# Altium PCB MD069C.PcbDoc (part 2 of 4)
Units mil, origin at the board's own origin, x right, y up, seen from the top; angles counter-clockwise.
Board outline 4569 x 3239 mil, 4 copper layers (Top Layer, Signal Layer 1, Signal Layer 2, Bottom Layer), stack 61.2 mil thick; 192 components, 101 nets, 567 pads, 224 vias.
Unrouted connection lines stored in the file: 7.

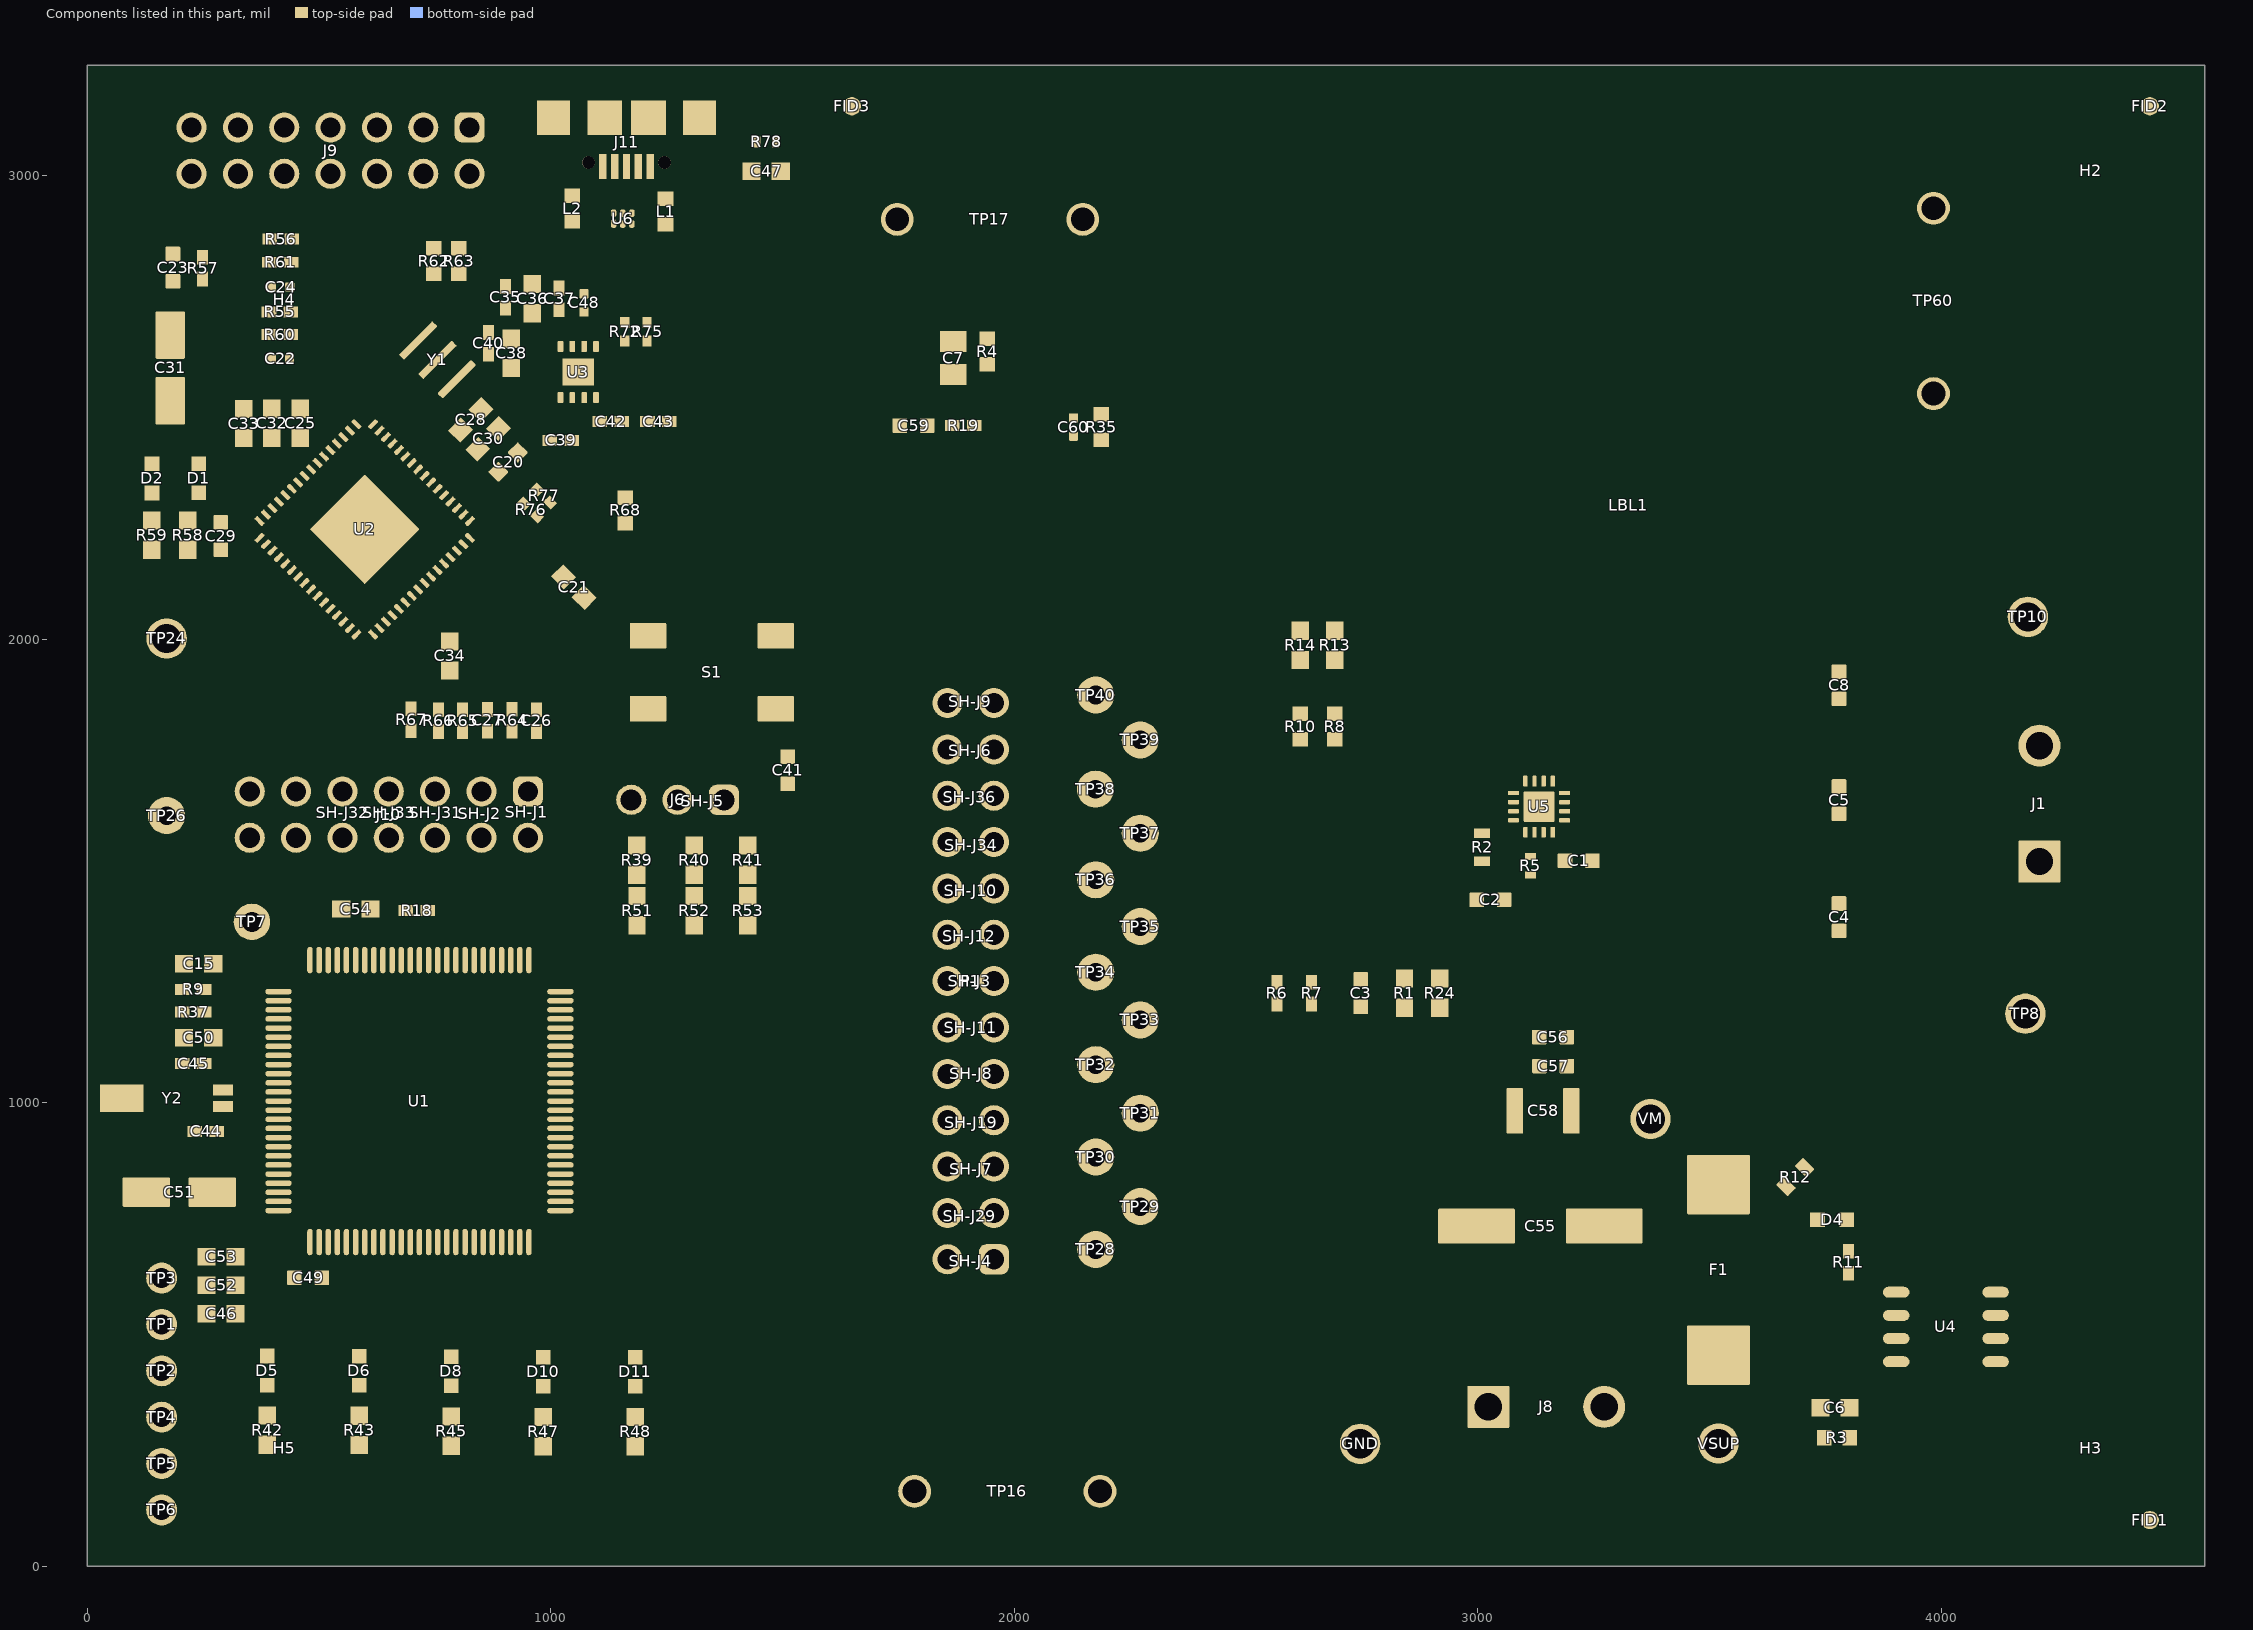
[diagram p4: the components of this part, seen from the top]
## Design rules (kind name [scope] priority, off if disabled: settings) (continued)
PolygonConnect PolygonConnect_5 [All vs IsNamedPolygon('TOP_LAYER_VM_P044')] p90: connectstyle=Direct reliefconductorwidth=10 reliefentries=4 polygonreliefangle="90 Angle" airgapwidth=10
PolygonConnect PolygonConnect_4 [All vs IsNamedPolygon('TOP_LAYER_VM_P046')] p91: connectstyle=Direct reliefconductorwidth=10 reliefentries=4 polygonreliefangle="90 Angle" airgapwidth=10
PolygonConnect PolygonConnect_3 [All vs IsNamedPolygon('TOP_LAYER_GND_P036') Or  IsNamedPolygon('TOP_LAYER_OUT2_P040') Or  IsNamedPolygon('TOP_LAYER_OUT1_P038')] p92: connectstyle=Direct reliefconductorwidth=10 reliefentries=4 polygonreliefangle="90 Angle" airgapwidth=10
PolygonConnect PolygonConnect_2 [InNet('EZFET_VBUS') vs IsNamedPolygon('TOP_LAYER_EZFET_VBUS_P008')] p93: connectstyle=Direct reliefconductorwidth=10 reliefentries=4 polygonreliefangle="90 Angle" airgapwidth=10
PolygonConnect PolygonConnect_1 [InNetClass('Power-Net') vs IsNamedPolygon('TOP_LAYER_EZFET_USB_SHIELD_P201')] p94: connectstyle=Direct reliefconductorwidth=10 reliefentries=4 polygonreliefangle="90 Angle" airgapwidth=10
PolygonConnect [All] p95: connectstyle=Direct reliefconductorwidth=10 reliefentries=4 polygonreliefangle="90 Angle" airgapwidth=10
RoutingVias ThermalPadVias [IsVia and InAnyComponent] p1: holewidth=7.87 width=19.68 viastyle="Through Hole" minholewidth=7.87 minwidth=19.68 maxholewidth=12.99 maxwidth=23.62
RoutingVias [All] p2: holewidth=16 width=34 viastyle="Through Hole" minholewidth=7.87 minwidth=26 maxholewidth=40 maxwidth=65
SilkToBoardRegionClearance [Not ((IsComment or IsDesignator) And (Hide <> 'False')) and not InRegion(1000,500,4000,800)] p1:
SilkToSilkClearance SilkToSilkClearance_Pb-FreeLogo [(HasFootprint('Pb-Free_Overlay_Medium') OR HasFootprint('Pb-Free_Overlay_Small')) vs (HasFootprint('Pb-Free_Overlay_Medium') OR HasFootprint('Pb-Free_Overlay_Small'))] p1: silktosilkclearance=0
SilkToSilkClearance [All] p2: silktosilkclearance=3.94
SilkToSolderMaskClearance SilkToComponentPadClearance [(IsPad or IsFill or IsRegion) and InAnycomponent] p1: minsilkscreentomaskgap=5 clearancetoexposedcopper=TRUE
SilkToSolderMaskClearance "Silk to Solder Mask Opening" [All] p2: minsilkscreentomaskgap=3.94 clearancetoexposedcopper=FALSE
SolderMaskExpansion [All] p1: expansion=1.97 istentingtop=FALSE
UnRoutedNet [All] p1: checkbadconnections=TRUE
Width [All] p1: maxlimit=65 minlimit=4 preferedwidth=15 minimp=50.000000 maximp=50.000000 favimp=50.000000 checkconnectedcopper=TRUE
14 further rules are at their usual default settings.

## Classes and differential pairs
component class FiducialMark: FID1 FID2 FID3
component class MD069C_Hardware: !PCB1 FID1 FID2 FID3 H2 H3 H4 H5 LBL1 Logo1 Logo2 Logo3 Logo4 LOGO5 ZZ1 ZZ2 ZZ3 ZZ4
component class MD069C: C1 C2 C3 C4 C5 C6 C7 C8 C15 C41 C44 C45 C46 C49 C50 C51 C52 C53 C54 C55 C56 C57 C58 C59 C60 D4 D5 D6 D8 D10 D11 F1 GND J1 J6 J8 P1 R1 R2 R3 R4 R5 R6 R7 R8 R9 R10 R11 R12 R13 R14 R18 R19 R24 R35 R37 R39 R40 R41 R42 R43 R45 R47 R48 R51 R52 R53 S1 SH-J1 SH-J2 SH-J3 SH-J4 SH-J5 SH-J6 SH-J7 SH-J8 SH-J9 SH-J10 SH-J11 SH-J12 SH-J19 SH-J36 TP1 TP2 TP3 TP4 TP5 TP6 TP7 TP8 TP10 TP16 TP17 TP24 TP26 TP28 TP29 TP30 TP31 TP32 TP33 TP34 TP35 TP36 TP37 TP38 TP39 TP40 TP60 U1 U4 U5 VM VSUP Y2
component class Shunt: SH-J1 SH-J2 SH-J3 SH-J4 SH-J5 SH-J6 SH-J7 SH-J8 SH-J9 SH-J10 SH-J11 SH-J12 SH-J19 SH-J29 SH-J31 SH-J32 SH-J33 SH-J34 SH-J36
net class Power-Net: EZFET_VBUS EZFET_VCC GND MCU_3V3
component class Header: J6 J9 J10
component class MD069C_ezFET: C20 C21 C22 C23 C24 C25 C26 C27 C28 C29 C30 C31 C32 C33 C34 C35 C36 C37 C38 C39 C40 C42 C43 C47 C48 D1 D2 J9 J10 J11 L1 L2 R55 R56 R57 R58 R59 R60 R61 R62 R63 R64 R65 R66 R67 R68 R72 R75 R76 R77 R78 SH-J29 SH-J31 SH-J32 SH-J33 SH-J34 U2 U3 U6 Y1
component class Logo: Logo2
component class AssemblyNote: ZZ1 ZZ2 ZZ3 ZZ4
component class Label: LBL1
differential pair USB_D: +USB_D_P -USB_D_N
differential pair EZFET_D: +EZFET_D_P -EZFET_D_N

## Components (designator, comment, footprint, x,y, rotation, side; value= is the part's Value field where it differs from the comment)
C1 "885012206120" FP-885012206120_0603-MFG 3217.89,1522.41 r180 top value=100nF
C2 "885012206120" FP-885012206120_0603-MFG 3027.54,1437.94 r0 top value=100nF
C3 "885012006085" FP-885012006085_0603-MFG 2747.83,1237 r90 top value=1nF
C4 "885012006085" FP-885012006085_0603-MFG 3779.61,1400.57 r90 top value=1nF
C5 "885012006085" FP-885012006085_0603-MFG 3779.61,1653.04 r270 top value=1nF
C6 "885012206095" 0603 3770.83,342.3 r0 top value=0.1uF
C7 "885012107011" 0805_150 1868.75,2606.85 r270 top value=22uF
C8 "885012006085" FP-885012006085_0603-MFG 3779.61,1901.04 r270 top value=1nF
C15 "885012206095" 0603 240.63,1300.54 r180 top value=0.1uF
C20 "885012106012" FP-885012106012_0603-MFG 908.28,2382.21 r225 top value=4.7µF
C21 "885012206095" 0603 1050.3,2112.7 r315 top value=0.1uF
C22 "885012005058" FP-885012005058_0402-MFG 417.27,2605.12 r0 top value=33pF
C23 "885012006085" FP-885012006085_0603-MFG 185.39,2801.89 r90 top value=1nF
C24 "885012005058" FP-885012005058_0402-MFG 417.71,2759.93 r0 top value=33pF
C25 "885012206095" 0603 459.95,2466.1 r90 top value=0.1uF
C26 "885012005055" 0402 969.55,1824.77 r270 top value=10pF
C27 "885012005055" 0402 863.56,1825 r270 top value=10pF
C28 "885012206048" 0603 827.93,2473.48 r45 top value=0.22uF
C29 "885012106008" FP-885012106008_0603-MFG 288.85,2222.71 r270 top value=470nF
C30 "885012206048" 0603 865.13,2432.41 r45 top value=0.22uF
C31 "875105240001" FP-875105240001_SMT_CAP_4MM3_4MM3-MFG 179.54,2585.63 r270 top value=10µF
C32 "885012206095" 0603 398.51,2466.1 r90 top value=0.1uF
C33 "885012206095" 0603 338.36,2465.67 r90 top value=0.1uF
C34 "885012206095" 0603 782.72,1964.12 r90 top value=0.1uF
C35 "885012105012" 0402 902.39,2737.6 r90 top value=1uF
C36 "885012206095" 0603 960.11,2735.17 r90 top value=0.1uF
C37 "885012205031" 0402 1018.24,2734.43 r90 top value=0.01uF
C38 "885012106018" 0603 914.83,2617.06 r90 top value=2.2uF
C39 "885012205031" 0402 1021.71,2429.23 r0 top value=0.01uF
C40 "885012105012" 0402 865.88,2638.47 r90 top value=1uF
C41 "885012006085" FP-885012006085_0603-MFG 1511.79,1717.67 r270 top value=1nF
C42 "885012005055" 0402 1129.9,2469.66 r180 top value=10pF
C43 "885012005055" 0402 1232.69,2469.66 r0 top value=10pF
C44 "885012005055" 0402 255.9,938.79 r0 top value=10pF
C45 "885012005055" 0402 228.65,1084.82 r180 top value=10pF
C46 "885012206095" 0603 289.02,545.23 r0 top value=0.1uF
C47 "885012206048" 0603 1465,3010.03 r0 top value=0.22uF
C48 "885012205018" FP-885012205018_0402-MFG 1072,2726 r90 top value=100nF
C49 "885012106008" FP-885012106008_0603-MFG 476.94,622.9 r0 top value=470nF
C50 "885012206095" 0603 240.63,1140.4 r180 top value=0.1uF
C51 "875105240001" FP-875105240001_SMT_CAP_4MM3_4MM3-MFG 198.98,807.41 r0 top value=10µF
C52 "885012206095" 0603 289.02,606.31 r180 top value=0.1uF
C53 "885012206095" 0603 289.02,667.92 r180 top value=0.1uF
C54 "885012206095" 0603 580.07,1418.17 r180 top value=0.1uF
C55 "865060653010" WCAP-ASLL_800x1050 3135.27,734.32 r180 top value=100uF
C56 "885012206120" FP-885012206120_0603-MFG 3162.41,1142.05 r0 top value=100nF
C57 "885012006085" FP-885012006085_0603-MFG 3162.93,1079.49 r0 top value=1nF
C58 "885012209069" FP-885012209069_1210-MFG 3141.12,982.93 r0 top value=1µF
C59 "885012006085" FP-885012006085_0603-MFG 1783,2461 r0 top value=1nF
C60 "885012005080" FP-885012005080_0402-MFG 2128,2458 r270 top value=100pF
D1 "150060RS75000" WL-SMCW_RED 241.42,2347.56 r270 top value=Red
D2 "150060VS75000" WL-SMCW_GREEN 140.2,2347.34 r270 top value=Green
D4 "150060VS75000" WL-SMCW_GREEN 3764.65,748.22 r180 top value=Green
D5 "150060VS75000" WL-SMCW_GREEN 388.79,422.48 r90 top value=Green
D6 "150060VS75000" WL-SMCW_GREEN 587.33,422 r90 top value=Green
D8 "150060VS75000" WL-SMCW_GREEN 785.86,421 r90 top value=Green
D10 "150060YS75000" WL-SMCW_YELLOW 984.4,420 r90 top value=Yellow
D11 "150060SS75000" WL-SMCW_RED 1182.94,420 r90 top value="Super Red"
F1 "0463030.ER" Fuse_0463 3519.57,639.72 r90 top
FID1 "Fiducial" Fiducial10-20 4450,100 r0 top
FID2 "Fiducial" Fiducial10-20 4450,3150 r0 top
FID3 "Fiducial" Fiducial10-20 1650,3150 r0 top
GND "5011" Keystone5011 2746.6,264.49 r270 top
H2 "SJ61A1" Bumpon_SJ61A1 4322.71,3010.82 r180 bottom
H3 "SJ61A1" Bumpon_SJ61A1 4322.71,254.91 r180 bottom
H4 "SJ61A1" Bumpon_SJ61A1 425.07,2733 r180 bottom
H5 "SJ61A1" Bumpon_SJ61A1 425.07,254.91 r180 bottom
J1 "691250610002" FP-691250610002_CONN_TERM_BLOCK2-MFG 4276.9,1633.9 r90 top
J6 "61300311121" WURTH_61300311121 1274,1653.91 r180 top
J8 "691250610002" FP-691250610002_CONN_TERM_BLOCK2-MFG 3136.18,279.35 r0 top
J9 "61301421121" Wurth_61301421121 525.43,3054.4 r270 top
J10 "61301421121" Wurth_61301421121 651,1622.02 r270 top
J11 "629105136821" 629105136821 1163.82,3125.32 r180 top
L1 "742792621" 0603L 1247.92,2922.74 r270 top value="140 ohm"
L2 "742792621" 0603L 1046.9,2929.31 r270 top value="140 ohm"
LBL1 "THT-14-423-10" Label_650x200 3324.42,2289.31 r0 top
Logo1 "CE Mark" CE_Mark_5mm 2152,2646 r0 top
Logo2 "Texas Instruments" TI_Stacked_Overlay_Medium 3108.15,2928.68 r0 top
Logo3 "FCC disclaimer" FCC_disclaimer 1552.47,194 r0 top
Logo4 "WEEE logo" WEEE_Minimum 2438,2655 r0 top
LOGO5 "CAUTION HOT SURFACE" IEC_HotSurface_Small 3513.09,1628.59 r0 top
P1 "61302621121" 61302621121 1906.3,1262.7 r90 top
R1 "RC0603JR-0710KL" 0603 2842,1237 r270 top value=10k
R2 "ERJ-3EKF1501V" 0603S 3009.48,1551.55 r270 top value=1.50k
R3 "Resistor" 0603L 3775.18,277.13 r180 top value=0
R4 "Resistor" 0603L 1942,2621 r90 top value=0
R5 "RC0402JR-070RL" 0402S 3113.71,1512 r90 top value=0
R6 "CRCW04022K21FKED" 0402 2567,1237 r270 top value=2.21k
R7 "CRCW04022K21FKED" 0402 2642,1237 r270 top value=2.21k
R8 "Resistor" 0603L 2692,1812 r90 top value=0
R9 "CRCW040210R0FKED" 0402 228.65,1245.03 r180 top value=10.0
R10 "Resistor" 0603L 2617,1812 r90 top value=0
R11 "CRCW0402680RJNED" 0402 3799.56,656.38 r90 top value=680
R12 "ERJ-3EKF5602V" FP-ERJ-3EKF5602V_0603-MFG 3685.21,840.11 r225 top value=56k
R13 "RC0603JR-0710KL" 0603 2692,1987 r90 top value=10k
R14 "RC0603JR-0710KL" 0603 2617,1987 r90 top value=10k
R18 "CRCW040247K0JNED" 0402 710.98,1414.72 r0 top value=47k
R19 "CRCW040247K0JNED" 0402 1890.54,2461.14 r0 top value=47k
R24 "RC0603JR-0710KL" 0603 2918.44,1237 r270 top value=10k
R35 "CRCW06034K99FKEA" 0603L 2188,2458 r270 top value=4.99k
R37 "CRCW040210R0FKED" 0402 228.65,1195.71 r0 top value=10.0
R39 "RC0603JR-0710KL" 0603 1186.18,1523.73 r270 top value=10k
R40 "RC0603JR-0710KL" 0603 1310,1523.73 r270 top value=10k
R41 "RC0603JR-0710KL" 0603 1425,1523.73 r270 top value=10k
R42 "RC0603JR-07560RL" 0603 388.5,294.21 r90 top value=560
R43 "CRCW0603330RJNEA" 0603 587.12,293.74 r90 top value=330
R45 "CRCW0603330RJNEA" 0603 785.74,291.74 r90 top value=330
R47 "CRCW0603330RJNEA" 0603 984.35,290.74 r90 top value=330
R48 "CRCW0603330RJNEA" 0603 1182.97,290.74 r90 top value=330
R51 "RC0603JR-0710KL" 0603 1186.54,1414.73 r270 top value=10k
R52 "RC0603JR-0710KL" 0603 1310,1414.73 r270 top value=10k
R53 "RC0603JR-0710KL" 0603 1425,1414.73 r270 top value=10k
R55 "RC0402FR-07220KL" 0402 416.06,2706.57 r180 top value=220k
R56 "CRCW0402240KFKED" 0402 417.71,2863.28 r180 top value=240k
R57 "CRCW040247K0JNED" 0402 249.39,2801.11 r270 top value=47k
R58 "RC0603JR-07470RL" 0603 217.05,2224.98 r90 top value=470
R59 "RC0603JR-07560RL" 0603 139.47,2224.94 r90 top value=560
R60 "RC0402FR-07220KL" 0402 415.82,2657.42 r0 top value=220k
R61 "CRCW0402150KFKED" 0402 417.32,2813.56 r0 top value=150k
R62 "Resistor" 0603L 748.08,2816.24 r270 top value=0
R63 "Resistor" 0603L 801.84,2815.99 r270 top value=0
R64 "CRCW040210R0FKED" 0402 916.87,1825.29 r270 top value=10.0
R65 "CRCW040210R0FKED" 0402 810.39,1824.44 r270 top value=10.0
R66 "CRCW040210R0FKED" 0402 757.89,1824.8 r270 top value=10.0
R67 "CRCW040210R0FKED" 0402 698.9,1826.38 r270 top value=10.0
R68 "Resistor" 0603L 1161.5,2278.36 r90 top value=0
R72 "CRCW040227R0JNED" 0402L 1159.94,2663.57 r270 top value=27
R75 "CRCW040227R0JNED" 0402L 1208.37,2663.57 r270 top value=27
R76 "CRCW04021K40FKED" 0402L 956.89,2279.33 r315 top value=1.40k
R77 "CRCW04021M00JNED" 0402L 985.35,2309.35 r135 top value=1.0Meg
R78 "CRCW040233K0JNED" 0402S 1465,3073 r180 top value=33k
S1 "430481025816" FP-430481025816_SMT_SW_6MM2_6MM2-MFG 1348,1929 r180 top
SH-J1 "60900213421" Wurth_60900213421 948.09,1626.66 r90 top
SH-J2 "60900213421" Wurth_60900213421 847.52,1624.26 r90 top
SH-J3 "60900213421" Wurth_60900213421 1904.17,1262.94 r180 top
SH-J4 "60900213421" Wurth_60900213421 1906.34,658.07 r180 top
SH-J5 "60900213421" Wurth_60900213421 1328.05,1650.57 r180 top
SH-J6 "60900213421" Wurth_60900213421 1905.63,1759.29 r180 top
SH-J7 "60900213421" Wurth_60900213421 1907.5,856.66 r180 top
SH-J8 "60900213421" Wurth_60900213421 1907.5,1062.47 r180 top
SH-J9 "60900213421" Wurth_60900213421 1904.93,1865.11 r180 top
SH-J10 "60900213421" Wurth_60900213421 1906.83,1457.42 r180 top
SH-J11 "60900213421" Wurth_60900213421 1905.95,1162.07 r180 top
SH-J12 "60900213421" Wurth_60900213421 1903.43,1359.73 r180 top
SH-J19 "60900213421" Wurth_60900213421 1907.5,957.23 r180 top
SH-J29 "60900213421" Wurth_60900213421 1904.26,755.54 r180 top
SH-J31 "60900213421" Wurth_60900213421 752,1626 r90 top
SH-J32 "60900213421" Wurth_60900213421 552,1626 r90 top
SH-J33 "60900213421" Wurth_60900213421 652,1626 r90 top
SH-J34 "60900213421" Wurth_60900213421 1907.02,1555.99 r180 top
SH-J36 "60900213421" Wurth_60900213421 1904.23,1659.03 r180 top
TP1 "TP_H0.45P0.75" TP_H045P075#1 161,516.01 r0 top
TP2 "TP_H0.45P0.75" TP_H045P075#2 161,429.43 r90 top
TP3 "TP_H0.45P0.75" TP_H045P075#3 161,610.59 r0 top
TP4 "TP_H0.45P0.75" TP_H045P075#4 161,322 r0 top
TP5 "TP_H0.45P0.75" TP_H045P075#5 161,243 r0 top
TP6 "TP_H0.45P0.75" TP_H045P075#6 161,131.34 r90 top
TP7 "TP_H0.45P0.75" TP_H045P075#7 355.7,1390.57 r90 top
TP8 "5012" Keystone5012 4181.57,1192.36 r90 top
TP10 "5012" Keystone5012 4187.05,2048.48 r90 top
TP16 "Jumper_2p" Harwin_D3082-05 1985.22,161.99 r180 top
TP17 "Jumper_2p" Harwin_D3082-05 1947.92,2906.03 r0 top
TP24 "5011" Keystone5011 171.7,2002 r0 top
TP26 "5003" Keystone5003 171.7,1619.87 r0 top
TP28 "5002" Keystone5002 2176.18,683.77 r0 top
TP29 "5002" Keystone5002 2272.18,776.47 r0 top
TP30 "5002" Keystone5002 2176.18,883.14 r0 top
TP31 "5002" Keystone5002 2272.18,977.79 r0 top
TP32 "5002" Keystone5002 2176.18,1082.5 r0 top
TP33 "5002" Keystone5002 2272.18,1179.1 r180 top
TP34 "5002" Keystone5002 2176.18,1281.86 r180 top
TP35 "5002" Keystone5002 2272.18,1380.42 r180 top
TP36 "5002" Keystone5002 2176.18,1481.23 r180 top
TP37 "5002" Keystone5002 2272.18,1581.73 r180 top
TP38 "5002" Keystone5002 2175.57,1676.89 r180 top
TP39 "5002" Keystone5002 2272.18,1783.05 r180 top
TP40 "5002" Keystone5002 2176.18,1879.95 r180 top
TP60 "Jumper_2p" Harwin_D3082-05 3983.31,2730.2 r270 top
U1 "MSP430F5338IPZ" PZT0100A_N 717.16,1004 r0 top
U2 "MSP430F5528IRGCT" RGC0064B 598.92,2237.21 r315 top
U3 "TPS73533DRBR" DRB0008A 1059.69,2576.77 r90 top
U4 "LM9036M-3.3/NOPB" D0008A_N 4010.2,516.66 r180 top
U5 "DRV8214RTER" RTE0016C-MFG 3132.46,1639.05 r90 top
U6 "TPD2E001DRYR" DRY0006A 1155.72,2907.58 r90 top
VM "5010" Keystone5010 3372.98,965.35 r270 top
VSUP "5010" Keystone5010 3519.57,265.13 r270 top
Y1 "CSTNR4M00GH5L000R0" MuRata_CSTNR 756.02,2602.94 r135 top
Y2 "MS3V-T1R 32.768KHZ +/-20PPM 12.5PF" XTAL_MS3V-T1R 184,1010 r180 top
ZZ1 "These assemblies are ESD sensitive, ESD precautions shall be observed." AssemblyNote 1269,-461 r0 top
ZZ2 "These assemblies must be clean and free from flux and all contaminants. Use of no clean flux is not acceptable." AssemblyNote 1260,-367 r0 top
ZZ3 "These assemblies must comply with workmanship standards IPC-A-610 Class 2, unless otherwise specified." AssemblyNote 1260,-564 r0 top
ZZ4 "This Assembly Note is for PCB labels only" AssemblyNoteLabel 1255,-663 r0 top

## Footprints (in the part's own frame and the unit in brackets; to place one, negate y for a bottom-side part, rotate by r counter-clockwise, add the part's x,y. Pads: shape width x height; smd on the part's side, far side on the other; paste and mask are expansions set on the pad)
0402 [mm] "0402 from SM-752 data"
  rect 0.8x0.6 smd: 1(-0.6,0) 2(0.6,0)
  silkscreen extent -1.22,-0.52 1.22,0.52, body extent -0.55,-0.3 0.55,0.3, height 0.6
0402L [mm] "0402 from SM-752 data"
  rect 0.6x0.5 smd: 1(-0.5,0) 2(0.5,0)
  body extent -0.55,-0.3 0.55,0.3, height 0.6
0402S [mil] "Based on C0402S footprint from PADS legacy"
  rect 15x24 smd: 1(-20,0) 2(20,0)
  body extent -22,-12 22,12, height 24
0603 [mm] "0603 from SM-752 data"
  rect 1x0.95 smd: 1(-0.8,0) 2(0.8,0)
  silkscreen extent -1.52,-0.69 1.52,0.69, body extent -0.87,-0.47 0.87,0.47, height 1
0603L [mm] "0603 from SM-752 data"
  rect 0.8x0.85 smd: 1(-0.7,0) 2(0.7,0)
  silkscreen extent -0.07,-0.33 0.07,0.33, body extent -0.87,-0.47 0.87,0.47, height 1
0603S [mil]
  rect 20x35 smd: 1(-30,0) 2(30,0)
  body extent -34,-19 34,19, height 39
0805_150 [mm] "0805 / 1.5 mm height"
  rect 1.15x1.45 smd: 1(-0.9,0) 2(0.9,0)
  silkscreen extent -0.1,-0.8 0.1,0.8, body extent -1.1,-0.72 1.1,0.72, height 1.5
61302621121 [mm] "Pin Header, pitch 2.54 mm, THT, Vertical, dual row, 26p"
  rrect50% 1.65x1.65 hole 1.1: 1(-15.24,-1.27)
  round 1.65 hole 1.1: 2(-15.24,1.27) 3(-12.7,-1.27) 4(-12.7,1.27) 5(-10.16,-1.27) 6(-10.16,1.27) 7(-7.62,-1.27) 8(-7.62,1.27) 9(-5.08,-1.27) 10(-5.08,1.27) 11(-2.54,-1.27) 12(-2.54,1.27) 13(0,-1.27) 14(0,1.27) 15(2.54,-1.27) 16(2.54,1.27) 17(5.08,-1.27) 18(5.08,1.27) 19(7.62,-1.27) 20(7.62,1.27) 21(10.16,-1.27) 22(10.16,1.27) 23(12.7,-1.27) 24(12.7,1.27) 25(15.24,-1.27) 26(15.24,1.27)
  silkscreen extent -16.66,-2.62 16.66,2.62, body extent -16.51,-2.54 16.51,2.54, height 8.59
629105136821 [mm] "Micro USB 2.0 SMT Type B Horizontal 5 Contacts"
  rect 0.4x1.35 smd: 1(-1.3,2.675) 2(-0.65,2.675) 3(0,2.675) 4(0.65,2.675) 5(1.3,2.675)
  round 0.7 hole 0.7 unplated: MH1(-2.075,2.45) MH2(2.075,2.45)
  rect 1.8x1.9 smd: Shell(-4,0) Shell(4,0)
  rect 1.9x1.9 smd: Shell(-1.2,0) Shell(1.2,0)
  silkscreen extent -4,-2.75 4,2.85, body extent -4,-2.73 4,3.17, height 2.69
AssemblyNote [mil] "Assembly Note"
AssemblyNoteLabel [mil] "Assembly Note for PCB Labels"
Bumpon_SJ61A1 [mil] "3M Cylindrical Bumpon black"
  round 1 on Mech4: 0(0,0)
  silkscreen extent -156,-156 156,156, body extent -156,-156 156,156, height 201
CE_Mark_5mm [mil] "Minimum text height for CE Mark"
  silkscreen extent -138,-98 138,98
D0008A_N [mm] "SOIC, 8-Leads, Body 4.9x3.9mm, Pitch 1.27mm, IPC Medium Density"
  oval 1.45x0.6 smd: 1(-2.725,1.905) 2(-2.725,0.635) 3(-2.725,-0.635) 4(-2.725,-1.905) 5(2.725,-1.905) 6(2.725,-0.635) 7(2.725,0.635) 8(2.725,1.905)
  silkscreen extent -3.3,-2.5 0.9,2.5, body extent -3,-2.45 3,2.45, height 1.63
DRB0008A [mm] "VSON-8"
  rrect32% 0.6x0.31 smd: 1(-1.4,0.975) 2(-1.4,0.325) 3(-1.4,-0.325) 4(-1.4,-0.975) 5(1.4,-0.975) 6(1.4,-0.325) 7(1.4,0.325) 8(1.4,0.975)
  rrect7% 1.5x1.75 smd paste-0.75: 9(0,0)
  Top Layer region: -0.7,-0.875 -0.49,-0.875 -0.471,-0.879 -0.455,-0.89 -0.444,-0.906 -0.44,-0.925 -0.44,-0.925 -0.44,-1.65 -0.436,-1.669 -0.425,-1.685 -0.409,-1.696 -0.39,-1.7 -0.39,-1.7 -0.26,-1.7 -0.241,-1.696 -0.225,-1.685 -0.214,-1.669 -0.21,-1.65 -0.21,-1.65 -0.21,-0.925 -0.206,-0.906 -0.195,-0.89 -0.179,-0.879 -0.16,-0.875 -0.16,-0.875 0.16,-0.875 0.179,-0.879 0.195,-0.89 0.206,-0.906 0.21,-0.925 0.21,-0.925 0.21,-1.65 0.21,-1.65 0.214,-1.669 0.225,-1.685 0.241,-1.696 0.26,-1.7 0.26,-1.7 0.39,-1.7 0.409,-1.696 0.425,-1.685 0.436,-1.669 0.44,-1.65 0.44,-1.65 0.44,-0.925 0.444,-0.906 0.455,-0.89 0.471,-0.879 0.49,-0.875 0.49,-0.875 0.7,-0.875 0.719,-0.871 0.735,-0.86 0.746,-0.844 0.75,-0.825 0.75,-0.825 0.75,0.825 0.746,0.844 0.735,0.86 0.719,0.871 0.7,0.875 0.7,0.875 0.49,0.875 0.471,0.879 0.455,0.89 0.444,0.906 0.44,0.925 0.44,0.925 0.44,1.65 0.436,1.669 0.425,1.685 0.409,1.696 0.39,1.7 0.39,1.7 0.26,1.7 0.241,1.696 0.225,1.685 0.214,1.669 0.21,1.65 0.21,1.65 0.21,1.65 0.21,0.925 0.206,0.906 0.195,0.89 0.179,0.879 0.16,0.875 0.16,0.875 -0.16,0.875 -0.179,0.879 -0.195,0.89 -0.206,0.906 -0.21,0.925 -0.21,0.925 -0.21,1.65 -0.214,1.669 -0.225,1.685 -0.241,1.696 -0.26,1.7 -0.26,1.7 -0.39,1.7 -0.409,1.696 -0.425,1.685 -0.436,1.669 -0.44,1.65 -0.44,1.65 -0.44,0.925 -0.444,0.906 -0.455,0.89 -0.471,0.879 -0.49,0.875 -0.49,0.875 -0.7,0.875 -0.719,0.871 -0.735,0.86 -0.746,0.844 -0.75,0.825 -0.75,0.825 -0.75,-0.825 -0.746,-0.844 -0.735,-0.86 -0.719,-0.871 -0.7,-0.875
  silkscreen extent -1.73,-1.73 1.73,1.73, body extent -1.5,-1.5 1.5,1.5, height 0.77
DRY0006A [mm] "USON-6"
  rrect67% 0.45x0.3 smd paste-0.05 mask-0.05: 1(-0.275,0.5)
  rrect67% 0.4x0.3 smd paste-0.05 mask-0.05: 2(-0.3,0) 3(-0.3,-0.5) 4(0.3,-0.5) 5(0.3,0) 6(0.3,0.5)
  body extent -0.5,-0.72 0.5,0.73, height 0.58
FCC_disclaimer [mil]
Fiducial10-20 [mm]
  round 1 smd mask+0.5: 1(0,0)
  Top Layer keep-out circle w1.178: c0,0 r0.5
FP-430481025816_SMT_SW_6MM2_6MM2-MFG [mm]
  rrect7% 2x1.4 smd paste+0 mask+0: 1(-3.5,2) 2(3.5,2) 3(-3.5,-2) 4(3.5,-2)
  silkscreen extent -5.18,-3.2 3.2,3.2, body extent -4.6,-3.3 4.6,3.3, height 0.25
FP-691250610002_CONN_TERM_BLOCK2-MFG [mm]
  rrect4% 2.3x2.3 hole 1.5 paste-2539.97 mask+0: 1(-2.875,1.65)
  round 2.3 hole 1.5 paste-2539.97 mask+0: 2(3.475,1.65)
  silkscreen extent -7.52,-6.3 6.85,6.3, body extent -6.95,-6.4 6.95,6.4, height 0.25
FP-875105240001_SMT_CAP_4MM3_4MM3-MFG [mm]
  rrect6% 2.6x1.6 smd paste+0 mask+0: 1(-1.8,0) 2(1.8,0)
  silkscreen extent -3.67,-2.25 2.25,2.25, body extent -3.35,-2.5 3.35,2.5, height 0.25
FP-885012005058_0402-MFG [mm]
  rrect20% 0.5x0.5 smd paste+0 mask+0: 1(-0.5,0) 2(0.5,0)
  silkscreen extent -0.53,-0.63 0.53,0.63, body extent -0.85,-0.38 0.85,0.38, height 0.25
FP-885012005080_0402-MFG [mm]
  rrect20% 0.5x0.5 smd paste+0 mask+0: 1(-0.5,0) 2(0.5,0)
  silkscreen extent -0.53,-0.63 0.53,0.63, body extent -0.85,-0.38 0.85,0.38, height 0.25
FP-885012006085_0603-MFG [mm]
  rrect13% 0.8x0.8 smd paste+0 mask+0: 1(-0.75,0) 2(0.75,0)
  silkscreen extent -0.85,-0.77 0.85,0.77, body extent -1.25,-0.55 1.25,0.55, height 0.25
FP-885012106008_0603-MFG [mm]
  rrect13% 0.8x0.8 smd paste+0 mask+0: 1(-0.75,0) 2(0.75,0)
  silkscreen extent -0.85,-0.77 0.85,0.77, body extent -1.25,-0.55 1.25,0.55, height 0.25
FP-885012106012_0603-MFG [mm]
  rrect13% 0.8x0.8 smd paste+0 mask+0: 1(-0.75,0) 2(0.75,0)
  silkscreen extent -0.85,-0.77 0.85,0.77, body extent -1.25,-0.55 1.25,0.55, height 0.25
FP-885012205018_0402-MFG [mm]
  rrect20% 0.5x0.5 smd paste+0 mask+0: 1(-0.5,0) 2(0.5,0)
  silkscreen extent -0.5,-0.63 0.5,0.63, body extent -0.85,-0.38 0.85,0.38, height 0.25
FP-885012206120_0603-MFG [mm]
  rrect13% 0.8x0.8 smd paste+0 mask+0: 1(-0.75,0) 2(0.75,0)
  silkscreen extent -0.85,-0.77 0.85,0.77, body extent -1.25,-0.55 1.25,0.55, height 0.25
FP-885012209069_1210-MFG [mm]
  rrect11% 0.9x2.5 smd paste+0 mask+0: 1(-1.55,0) 2(1.55,0)
  silkscreen extent -0.72,-1.4 0.72,1.4, body extent -2.1,-1.5 2.1,1.5, height 0.25
FP-ERJ-3EKF5602V_0603-MFG [mm]
  rrect15% 0.65x0.9 smd paste+0 mask+0: 1(-0.725,0) 2(0.725,0)
  silkscreen extent 0,-0.48 0,0.48, body extent -1.15,-0.58 1.15,0.58, height 0.25
Fuse_0463 [mm] "SMD, 2-Leads, Body 10.1x3.12mm"
  rrect3% 3.25x3.43 smd: 1(-4.675,0) 2(4.675,0)
  silkscreen extent -2.6,-1.5 2.6,1.5, body extent -5.05,-1.56 5.05,1.56, height 3.12
Harwin_D3082-05 [mm] "Shorting Plug, 10.16mm spacing, TH"
  round 1.8 hole 1.3: 1(-5.08,0) 2(5.08,0)
  silkscreen extent -3.9,-0.53 3.9,0.53, body extent -5.6,-0.52 5.61,0.52, height 6.63
IEC_HotSurface_Small [mil]
  silkscreen extent -107,-93 107,92
Keystone5002 [mil] "For Keystone 500x miniature loop terminals"
  round 80 hole 40: 1(0,0)
  silkscreen extent -52,-52 52,52, body extent -49,-49 49,49, height 182
Keystone5003 [mil] "For Keystone 500x miniature loop terminals"
  round 80 hole 40: 1(0,0)
  silkscreen extent -52,-52 52,52, body extent -49,-49 49,49, height 182
Keystone5010 [mil] "Keystone Multipurpose loops"
  round 87 hole 63: 1(0,0)
  silkscreen extent -70,-70 70,70, body extent -63,-63 63,62, height 319
Keystone5011 [mil] "Keystone Multipurpose loops"
  round 87 hole 63: 1(0,0)
  silkscreen extent -70,-70 70,70, body extent -63,-63 63,62, height 319
Keystone5012 [mil] "Keystone Multipurpose loops"
  round 87 hole 63: 1(0,0)
  silkscreen extent -70,-70 70,70, body extent -63,-63 63,62, height 319
Label_650x200 [mil] "Thermal Transfer Label"
  round 1 on Mech13: 0(0,0)
  silkscreen extent -325,-100 325,100, body extent -325,-100 325,100, height 1
MuRata_CSTNR [mm] "SMD, 3-Leads, Body 4.5x2mm, Pitch 1.5mm"
  rrect25% 0.4x2.6 smd: 1(-1.5,0) 2(0,0) 3(1.5,0)
  body extent -2.3,-1.05 2.3,1.05, height 1.2
PZT0100A_N [mm] "QFP, 100-Leads, Body 14x14mm, Pitch 0.50mm, IPC Medium Density"
  oval 1.45x0.3 smd: 1(-7.725,6) 2(-7.725,5.5) 3(-7.725,5) 4(-7.725,4.5) 5(-7.725,4) 6(-7.725,3.5) 7(-7.725,3) 8(-7.725,2.5) 9(-7.725,2) 10(-7.725,1.5) 11(-7.725,1) 12(-7.725,0.5) 13(-7.725,0) 14(-7.725,-0.5) 15(-7.725,-1) 16(-7.725,-1.5) 17(-7.725,-2) 18(-7.725,-2.5) 19(-7.725,-3) 20(-7.725,-3.5) 21(-7.725,-4) 22(-7.725,-4.5) 23(-7.725,-5) 24(-7.725,-5.5) 25(-7.725,-6) 51(7.725,-6) 52(7.725,-5.5) 53(7.725,-5) 54(7.725,-4.5) 55(7.725,-4) 56(7.725,-3.5) 57(7.725,-3) 58(7.725,-2.5) 59(7.725,-2) 60(7.725,-1.5) 61(7.725,-1) 62(7.725,-0.5) 63(7.725,0) 64(7.725,0.5) 65(7.725,1) 66(7.725,1.5) 67(7.725,2) 68(7.725,2.5) 69(7.725,3) 70(7.725,3.5) 71(7.725,4) 72(7.725,4.5) 73(7.725,5) 74(7.725,5.5) 75(7.725,6)
  oval 0.3x1.45 smd: 26(-6,-7.725) 27(-5.5,-7.725) 28(-5,-7.725) 29(-4.5,-7.725) 30(-4,-7.725) 31(-3.5,-7.725) 32(-3,-7.725) 33(-2.5,-7.725) 34(-2,-7.725) 35(-1.5,-7.725) 36(-1,-7.725) 37(-0.5,-7.725) 38(0,-7.725) 39(0.5,-7.725) 40(1,-7.725) 41(1.5,-7.725) 42(2,-7.725) 43(2.5,-7.725) 44(3,-7.725) 45(3.5,-7.725) 46(4,-7.725) 47(4.5,-7.725) 48(5,-7.725) 49(5.5,-7.725) 50(6,-7.725) 76(6,7.725) 77(5.5,7.725) 78(5,7.725) 79(4.5,7.725) 80(4,7.725) 81(3.5,7.725) 82(3,7.725) 83(2.5,7.725) 84(2,7.725) 85(1.5,7.725) 86(1,7.725) 87(0.5,7.725) 88(0,7.725) 89(-0.5,7.725) 90(-1,7.725) 91(-1.5,7.725) 92(-2,7.725) 93(-2.5,7.725) 94(-3,7.725) 95(-3.5,7.725) 96(-4,7.725) 97(-4.5,7.725) 98(-5,7.725) 99(-5.5,7.725) 100(-6,7.725)
  silkscreen extent -8.1,-8.2 8.1,8.2, body extent -8.01,-8.01 8.01,8.01, height 1.6
RGC0064B [mm] "VQFN-64"
  rrect42% 0.6x0.24 smd mask+0.07: 1(-4.4,3.75) 2(-4.4,3.25) 3(-4.4,2.75) 4(-4.4,2.25) 5(-4.4,1.75) 6(-4.4,1.25) 7(-4.4,0.75) 8(-4.4,0.25) 9(-4.4,-0.25) 10(-4.4,-0.75) 11(-4.4,-1.25) 12(-4.4,-1.75) 13(-4.4,-2.25) 14(-4.4,-2.75) 15(-4.4,-3.25) 16(-4.4,-3.75) 33(4.4,-3.75) 34(4.4,-3.25) 35(4.4,-2.75) 36(4.4,-2.25) 37(4.4,-1.75) 38(4.4,-1.25) 39(4.4,-0.75) 40(4.4,-0.25) 41(4.4,0.25) 42(4.4,0.75) 43(4.4,1.25) 44(4.4,1.75) 45(4.4,2.25) 46(4.4,2.75) 47(4.4,3.25) 48(4.4,3.75)
  rrect42% 0.24x0.6 smd mask+0.07: 17(-3.75,-4.4) 18(-3.25,-4.4) 19(-2.75,-4.4) 20(-2.25,-4.4) 21(-1.75,-4.4) 22(-1.25,-4.4) 23(-0.75,-4.4) 24(-0.25,-4.4) 25(0.25,-4.4) 26(0.75,-4.4) 27(1.25,-4.4) 28(1.75,-4.4) 29(2.25,-4.4) 30(2.75,-4.4) 31(3.25,-4.4) 32(3.75,-4.4) 49(3.75,4.4) 50(3.25,4.4) 51(2.75,4.4) 52(2.25,4.4) 53(1.75,4.4) 54(1.25,4.4) 55(0.75,4.4) 56(0.25,4.4) 57(-0.25,4.4) 58(-0.75,4.4) 59(-1.25,4.4) 60(-1.75,4.4) 61(-2.25,4.4) 62(-2.75,4.4) 63(-3.25,4.4) 64(-3.75,4.4)
  rrect2% 4.25x4.25 smd paste-2.112: 65(0,0)
  body extent -4.5,-4.5 4.5,4.5, height 1
RTE0016C-MFG [mm]
  rrect42% 0.6x0.24 smd paste+0 mask+0: 1(-1.4,0.75) 2(-1.4,0.25) 3(-1.4,-0.25) 4(-1.4,-0.75) 9(1.4,-0.75) 10(1.4,-0.25) 11(1.4,0.25) 12(1.4,0.75)
  rrect42% 0.24x0.6 smd paste+0 mask+0: 5(-0.75,-1.4) 6(-0.25,-1.4) 7(0.25,-1.4) 8(0.75,-1.4) 13(0.75,1.4) 14(0.25,1.4) 15(-0.25,1.4) 16(-0.75,1.4)
  rrect6% 1.68x1.68 smd paste-1000 mask+0: 17(0,0)
  silkscreen extent -2.23,-1.55 1.55,1.55, body extent -1.8,-1.8 1.8,1.8, height 0.25
TI_Stacked_Overlay_Medium [mil]
  silkscreen extent -576,-136 576,134
TP_H045P075#1 [mm] "TP_H0.45P0.75"
  round 1.7 hole 1.1: 1(0,0.152)
TP_H045P075#2 [mm] "TP_H0.45P0.75"
  round 1.7 hole 1.1: 1(-0.189,0)
TP_H045P075#3 [mm] "TP_H0.45P0.75"
  round 1.7 hole 1.1: 1(0,0.29)
TP_H045P075#4 [mm] "TP_H0.45P0.75"
  round 1.7 hole 1.1: 1(0,0)
TP_H045P075#5 [mm] "TP_H0.45P0.75"
  round 1.7 hole 1.1: 1(0,-0.533)
TP_H045P075#6 [mm] "TP_H0.45P0.75"
  round 1.7 hole 1.1: 1(-0.237,0)
TP_H045P075#7 [mm] "TP_H0.45P0.75"
  round 2 hole 1.1: 1(0,0)
WCAP-ASLL_800x1050 [mm] "SMD, 2-Leads, Dia 8mm"
  rrect5% 4.2x1.9 smd: 1(-3.5,0) 2(3.5,0)
  body extent -4.3,-4.25 4.3,4.25, height 10.51
WEEE_Minimum [mil] "WEEElie bin"
  silkscreen extent -95,-172 99,104
WL-SMCW_GREEN [mm] "WURTH"
  rect 0.8x0.8 smd: 1(-0.8,0) 2(0.8,0)
  silkscreen extent -1.9,-0.8 1.2,0.8, body extent -0.85,-0.45 0.85,0.45, height 0.8
WL-SMCW_RED [mm] "WURTH"
  rect 0.8x0.8 smd: 1(-0.8,0) 2(0.8,0)
  silkscreen extent -1.9,-0.8 1.2,0.8, body extent -0.85,-0.45 0.85,0.45, height 0.8
WL-SMCW_YELLOW [mm] "WURTH"
  rect 0.8x0.8 smd: 1(-0.8,0) 2(0.8,0)
  silkscreen extent -1.9,-0.8 1.2,0.8, body extent -0.85,-0.45 0.85,0.45, height 0.8
Wurth_60900213421 [mil] "Shunt, 2.54mm, Black"
  round 1 on Mech3: 0(0,0)
  body extent -98,-48 98,48, height 338
WURTH_61300311121 [mm] "Header, 2.54mm, 3x1, TH"
  rrect50% 1.65x1.65 hole 1.15: 1(-2.54,0)
  round 1.65 hole 1.15: 2(0,0) 3(2.54,0)
  body extent -3.81,-1.27 3.81,1.27, height 8.54
Wurth_61301421121 [mm] "Header, 2.54mm, 7x2, TH"
  rrect50% 1.65x1.65 hole 1.1: 1(-1.27,7.62)
  round 1.65 hole 1.1: 2(1.27,7.62) 3(-1.27,5.08) 4(1.27,5.08) 5(-1.27,2.54) 6(1.27,2.54) 7(-1.27,0) 8(1.27,0) 9(-1.27,-2.54) 10(1.27,-2.54) 11(-1.27,-5.08) 12(1.27,-5.08) 13(-1.27,-7.62) 14(1.27,-7.62)
  body extent -2.54,-8.89 2.54,8.89, height 8.55
XTAL_MS3V-T1R [mm] "Micro Crystal Switzerland recommended land pattern"
  rect 1.1x0.6 smd: 1(-2.775,0.45) 2(-2.775,-0.45)
  rect 2.4x1.5 smd: 3(2.775,0)
  silkscreen extent -1.9,-0.74 1.2,0.74, body extent -3.05,-0.74 3.65,0.74, height 1.42

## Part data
C1 C2 C56: library part CMP-0097294-1, "0.1 µF ±10% 100V Ceramic Capacitor X7R 0603 (1608 Metric)", Digikey Part Number=732-885012206120TR-ND, Manufacturer="Wurth Electronics", Mouser Part Number=710-885012206120, Operating Temperature Range="-55°C to +125°C", TempCo=15%, Temperature Characteristic=X7R, Tolerance_%=10%, ValueDisplayed=100nF
C3 C4 C5 C8 C23 C41 C57 C59: library part CMP-0097311-1, "1000 pF ±5% 100V Ceramic Capacitor C0G, NP0 0603 (1608 Metric)", Digikey Part Number=732-12187-1-ND, Manufacturer="Wurth Electronics", Mouser Part Number=710-885012006085, Operating Temperature Range="-55°C to +125°C", TempCo=30ppm/°C, Temperature Characteristic=NP0, Tolerance_%=5%, ValueDisplayed=1nF
C6 C15 C21 C25 C32 C33 C34 C36 C46 C50 C52 C53 C54: library part CMP-0006837-4, "CAP, CERM, 0.1 uF, 50 V, +/- 10%, X7R, 0603", Cap_Case=0603, Manufacturer="Wurth Elektronik", TempCo=X7R, Tolerance_%=10%, Value1=Unknown, Value2=50V, ValueDisplayed=0.1uF
C7: library part CMP-0078153-1, "CAP, CERM, 22 µF, 10 V,+/- 20%, X5R, 0805", Cap_Case=0805, Manufacturer="Wurth Elektronik", Supplier Part Number 1=732-7621-1-ND, TempCo=X5R, Tolerance_%=20%, Value2=10V, ValueDisplayed=22µF
C20: library part CMP-0097305-1, "4.7 µF ±20% 10V Ceramic Capacitor X5R 0603 (1608 Metric)", Digikey Part Number=732-7909-1-ND, Manufacturer="Wurth Electronics", Mouser Part Number=710-885012106012, Operating Temperature Range="-55°C to +85°C", TempCo=15%, Temperature Characteristic=X5R, Tolerance_%=20%, ValueDisplayed=4.7uF
C22 C24: library part CMP-0097306-1, "33 pF ±5% 50V Ceramic Capacitor C0G, NP0 0402 (1005 Metric)", Digikey Part Number=732-7472-1-ND, Manufacturer="Wurth Electronics", Mouser Part Number=710-885012005058, Operating Temperature Range="-55°C to +125°C", TempCo=30ppm/°C, Temperature Characteristic=NP0, Tolerance_%=5%, ValueDisplayed=33pF
C26 C27 C42 C43 C44 C45: library part CMP-0006215-2, "CAP, CERM, 10 pF, 50 V, +/- 5%, C0G/NP0, 0402", Cap_Case=0402, Manufacturer="Wurth Elektronik", Supplier Part Number 1=732-7469-1-ND, TempCo=C0G/NP0, Tolerance_%=5%, Value1=Unknown, Value2=50V, ValueDisplayed=10pF
C28 C30 C47: library part CMP-0006830-4, "CAP, CERM, 0.22 uF, 16 V, +/- 10%, X7R, 0603", Cap_Case=0603, Manufacturer="Wurth Elektronik", Supplier Part Number 1=710-885012206048, TempCo=X7R, Tolerance_%=10%, Value1=Unknown, Value2=16V, ValueDisplayed=0.22uF
C29 C49: library part CMP-0097299-1, "0.47 µF ±20% 10V Ceramic Capacitor X5R 0603 (1608 Metric)", Digikey Part Number=732-7905-1-ND, Manufacturer="Wurth Electronics", Mouser Part Number=710-885012106008, Operating Temperature Range="-55°C to +85°C", TempCo=15%, Temperature Characteristic=X5R, Tolerance_%=20%, ValueDisplayed=470nF
C31 C51: library part CMP-0097340-1, "Alum. Polymer Cap 10µF 10V 5.5mmV-Chip WCAP-PSLP Series Lifetime 2000h +105°C", Digikey Part Number=732-6401-1-ND, Leakage Current=300uA, Manufacturer="Wurth Electronics", Mouser Part Number=710-875105240001, Operating Temperature Range="-55°C to +105°C", Tolerance_%=20%, ValueDisplayed=10uF
C35 C40: library part CMP-0064924-2, "CAP, CERM, 1 uF, 10 V,+/- 20%, X5R, 0402", Cap_Case=0402, Manufacturer="Wurth Elektronik", Supplier Part Number 1=732-7489-1-ND, TempCo=X5R, Tolerance_%=20%, Value1=Unknown, Value2=10V, ValueDisplayed=1uF
C37 C39: library part CMP-0006227-2, "CAP, CERM, 0.01 uF, 16 V, +/- 10%, X7R, 0402", Cap_Case=0402, Manufacturer="Wurth Elektronik", Supplier Part Number 1=710-885012205031, TempCo=X7R, Tolerance_%=10%, Value1=Unknown, Value2=16V, ValueDisplayed=0.01uF
C38: library part CMP-0006825-5, "CAP, CERM, 2.2 uF, 16 V, +/- 20%, X5R, 0603", Cap_Case=0603, Manufacturer="Wurth Elektronik", Supplier Part Number 1=732-7915-1-ND, TempCo=X5R, Tolerance_%=20%, Value1=Unknown, Value2=16V, ValueDisplayed=2.2uF
C48: library part CMP-0090362-1, "0.1µF ±10% 10V Ceramic Capacitor X7R 0402 (1005 Metric)", Digikey Part Number=732-7513-1-ND, Manufacturer="Wurth Electronics", Mouser Part Number=710-885012205018, Operating Temperature Range="-55°C to +125°C", TempCo=15%, Temperature Characteristic=X7R, Tolerance_%=10%, ValueDisplayed=100000pF
C55: library part CMP-0081644-1, "CAP, AL, 100 µF, 50 V, +/- 20%, SMD", Cap_Case=8X10.5mm, Manufacturer="Wurth Elektronik", Supplier Part Number 1=732-8550-1-ND, Tolerance_%=20%, Value2=50V, ValueDisplayed=100µF
C58: library part CMP-0097312-1, "1 µF ±10% 100V Ceramic Capacitor X7R 1210 (3225 Metric)", Manufacturer="Wurth Electronics", Operating Temperature Range="-55°C to +125°C", TempCo=15%, Temperature Characteristic=X7R, Tolerance_%=10%, ValueDisplayed=1uF
C60: library part CMP-0097308-1, "100 pF ±5% 100V Ceramic Capacitor C0G, NP0 0402 (1005 Metric)", Digikey Part Number=732-12055-1-ND, Manufacturer="Wurth Electronics", Mouser Part Number=710-885012005080, Operating Temperature Range="-55°C to +125°C", TempCo=30ppm/°C, Temperature Characteristic=NP0, Tolerance_%=5%, ValueDisplayed=100pF
D1: library part CMP-0002947-3, "LED, Red, SMD", Color=Red, Manufacturer="Wurth Elektronik", Power_TotalModule=72mW, Value1=0.072W, Value2=2V
D2 D4 D5 D6 D8: library part CMP-0002894-2, "LED, Green, SMD", Color=green, Manufacturer="Wurth Elektronik", Value1=W, Value2=2V
D10: library part CMP-0002892-3, "LED, Yellow, SMD", Color=yellow, Manufacturer="Wurth Elektronik", Value1=W, Value2=2V
D11: library part CMP-0002893-1, "LED, Super Red, SMD", Color="super red", Manufacturer="Wurth Elektronik", Supplier Part Number 1=732-4979-1-ND, Value1=W, Value2=1.9V
F1: library part CMP-0077200-3, "Fuse, 30 A, 250 VAC, 100 VDC, SMD", Irating_A=30A, Manufacturer=Littelfuse, Supplier Part Number 1=F6439CT-ND
FID1 FID2 FID3: library part CMP-0077181-1, "Fiducial mark.  There is nothing to buy or mount.", Manufacturer=N/A
GND TP24: library part CMP-0055148-2, "Test Point, Multipurpose, Black, TH", Color=Black, Manufacturer="Keystone Electronics", PartNumber=36-5011-ND
H2 H3 H4 H5: library part CMP-0003621-1, "Bumpon, Cylindrical, 0.312 X 0.200, Black", Manufacturer=3M, Supplier Part Number 1=SJ5746-0-ND
J1 J8: library part CMP-0093233-2, "2 Position Wire to Board Terminal Block Horizontal with Board 0.250\" (6.35mm) Through Hole", Current_A=32A, Digikey Part Number=732-691250610002-ND, Manufacturer="Wurth Electronics", Mouser Part Number=710-691250610002, Operating Temperature Range="-32°C to +120°C", Voltage_V=450V
J6: library part CMP-0054796-4, "Header, 2.54 mm, 3x1, Gold, TH", Manufacturer="Wurth Elektronik", Supplier Part Number 1=732-5316-ND
J9 J10: library part CMP-0086014-1, "Header, 2.54mm, 7x2, Gold, TH", Color=Black, Current_A=3A, Manufacturer="Wurth Elektronik", Voltage_V=250V
J11: library part CMP-1502-03253-2, "USB - micro B USB 2.0 Receptacle Connector 5 Position Surface Mount, Right Angle", Color=Black, Contact Resistance=30mΩ, Current Rating=1A, Flammability Rating="UL94 V-0", Insulation Resistance=1GΩ, Manufacturer="Wurth Elektronik", Max Operating Temperature=105°C, Min Operating Temperature=-40°C, Operating Supply Voltage=30V
L1 L2: library part CMP-0003184-2, "Ferrite Bead, 140 ohm @ 100 MHz, 0.55 A, 0603", Manufacturer="Wurth Elektronik", Supplier Part Number 1=732-4663-1-ND, Value1="0.2 ohm", Value2=0.55A, ValueDisplayed="140 ohm"
LBL1: library part CMP-0003625-1, "Thermal Transfer Printable Labels, 0.650\" W x 0.200\" H - 10,000 per roll", Manufacturer=Brady, Supplier Part Number 1=97C5133
Logo1: library part CMP-0074844-1
Logo2: library part CMP-0074838-1, "Texas Instrument Corporate Signature"
Logo3: library part CMP-0074847-1, "FCC_disclaimer"
Logo4: library part CMP-0074769-3, Manufacturer="Texas Instruments"
LOGO5: library part CMP-0074837-2, "IEC 61010-1 Hot Surface Warning", Manufacturer="Texas Instruments"
P1: library part CMP-1502-01114-2, "Header, 2.54mm, 13x2, Gold, TH", Color=Black, Contact Resistance=20mΩ, Current Rating=3A, Manufacturer="Wurth Elektronik", Operating Supply Voltage=250V
R1 R13 R14 R24 R39 R40 R41 R51 R52 R53: library part CMP-0025886-5, "RES, 10 k, 5%, 0.1 W, 0603", Manufacturer=Yageo, Power_W=100mW, Supplier Part Number 1=311-10KGRCT-ND, TempCo="100 ppm/C", Tolerance_%=5%, Value2=0.1W, Value_Code=10k0, ValueDisplayed=10k
R2: library part CMP-0022689-3, "RES, 1.50 k, 1%, 0.1 W, 0603", Manufacturer=Panasonic, Power_W=100mW, Supplier Part Number 1=P1.50KHCT-ND, TempCo="100 ppm/C", Tolerance_%=1%, Value2=0.1W, Value_Code=1k50, ValueDisplayed=1.50k
R3 R4 R8 R10 R62 R63 R68: library part CMP-0025697-4, "RES, 0, 5%, 0.1 W, AEC-Q200 Grade 0, 0603", Manufacturer=Vishay-Dale, PartNumber=CRCW06030000Z0EA, Power_W=100mW, Supplier Part Number 1=541-0.0GCT-ND, TempCo="200 ppm/C", Tolerance_%=5%, Value2=0.1W, Value_Code=0000, ValueDisplayed=0
R5: library part CMP-0027004-2, "RES, 0, 5%, 0.063 W, 0402", Manufacturer="Yageo America", Power_W=63mW, Supplier Part Number 1=311-0.0JRCT-ND, TempCo="200 ppm/C", Tolerance_%=5%, Value2=0.063W, Value_Code=0000, ValueDisplayed=0
R6 R7: library part CMP-0026232-2, "RES, 2.21 k, 1%, 0.063 W, AEC-Q200 Grade 0, 0402", Manufacturer=Vishay-Dale, Power_W=63mW, Supplier Part Number 1=541-2.21KLCT-ND, TempCo="100 ppm/C", Tolerance_%=1%, Value2=0.063W, Value_Code=2k21, ValueDisplayed=2.21k
R9 R37 R64 R65 R66 R67: library part CMP-0025963-3, "RES, 10.0, 1%, 0.063 W, AEC-Q200 Grade 0, 0402", Manufacturer=Vishay-Dale, Power_W=63mW, Supplier Part Number 1=541-10.0LCT-ND, TempCo="100 ppm/C", Tolerance_%=1%, Value2=0.063W, Value_Code=10R0, ValueDisplayed=10.0
R11: library part CMP-0026962-3, "RES, 680, 5%, 0.063 W, AEC-Q200 Grade 0, 0402", Manufacturer=Vishay-Dale, Power_W=63mW, Supplier Part Number 1=541-680JCT-ND, TempCo="200 ppm/C", Tolerance_%=5%, Value2=0.063W, Value_Code=680R, ValueDisplayed=680
R12: library part CMP-0094677-1, "56 kOhms ±1% 0.1W, 1/10W Chip Resistor 0603 (1608 Metric) Automotive AEC-Q200 Thick Film", Digikey Part Number=P56.0KHCT-ND, Manufacturer=Panasonic, Mouser Part Number=667-ERJ-3EKF5602V, Operating Temperature Range="-55°C to +155°C", Power_W=100mW, TempCo=100ppm/°C, Tolerance_%=1%
R18 R19 R57: library part CMP-0026935-3, "RES, 47 k, 5%, 0.063 W, AEC-Q200 Grade 0, 0402", Manufacturer=Vishay-Dale, Power_W=63mW, Supplier Part Number 1=541-47KJCT-ND, TempCo="200 ppm/C", Tolerance_%=5%, Value2=0.063W, Value_Code=47k0, ValueDisplayed=47k
R35: library part CMP-0022458-4, "RES, 4.99 k, 1%, 0.1 W, AEC-Q200 Grade 0, 0603", Manufacturer=Vishay-Dale, Power_W=100mW, Supplier Part Number 1=541-4.99KHCT-ND, TempCo="100 ppm/C", Tolerance_%=1%, Value2=0.1W, Value_Code=4k99, ValueDisplayed=4.99k
R42 R59: library part CMP-0025930-5, "RES, 560, 5%, 0.1 W, 0603", Manufacturer=Yageo, Power_W=100mW, Supplier Part Number 1=311-560GRCT-ND, TempCo="100 ppm/C", Tolerance_%=5%, Value2=0.1W, Value_Code=560R, ValueDisplayed=560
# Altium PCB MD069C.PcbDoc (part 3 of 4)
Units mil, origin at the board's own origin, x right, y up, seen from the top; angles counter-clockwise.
Board outline 4569 x 3239 mil, 4 copper layers (Top Layer, Signal Layer 1, Signal Layer 2, Bottom Layer), stack 61.2 mil thick; 192 components, 101 nets, 567 pads, 224 vias.
Unrouted connection lines stored in the file: 7.

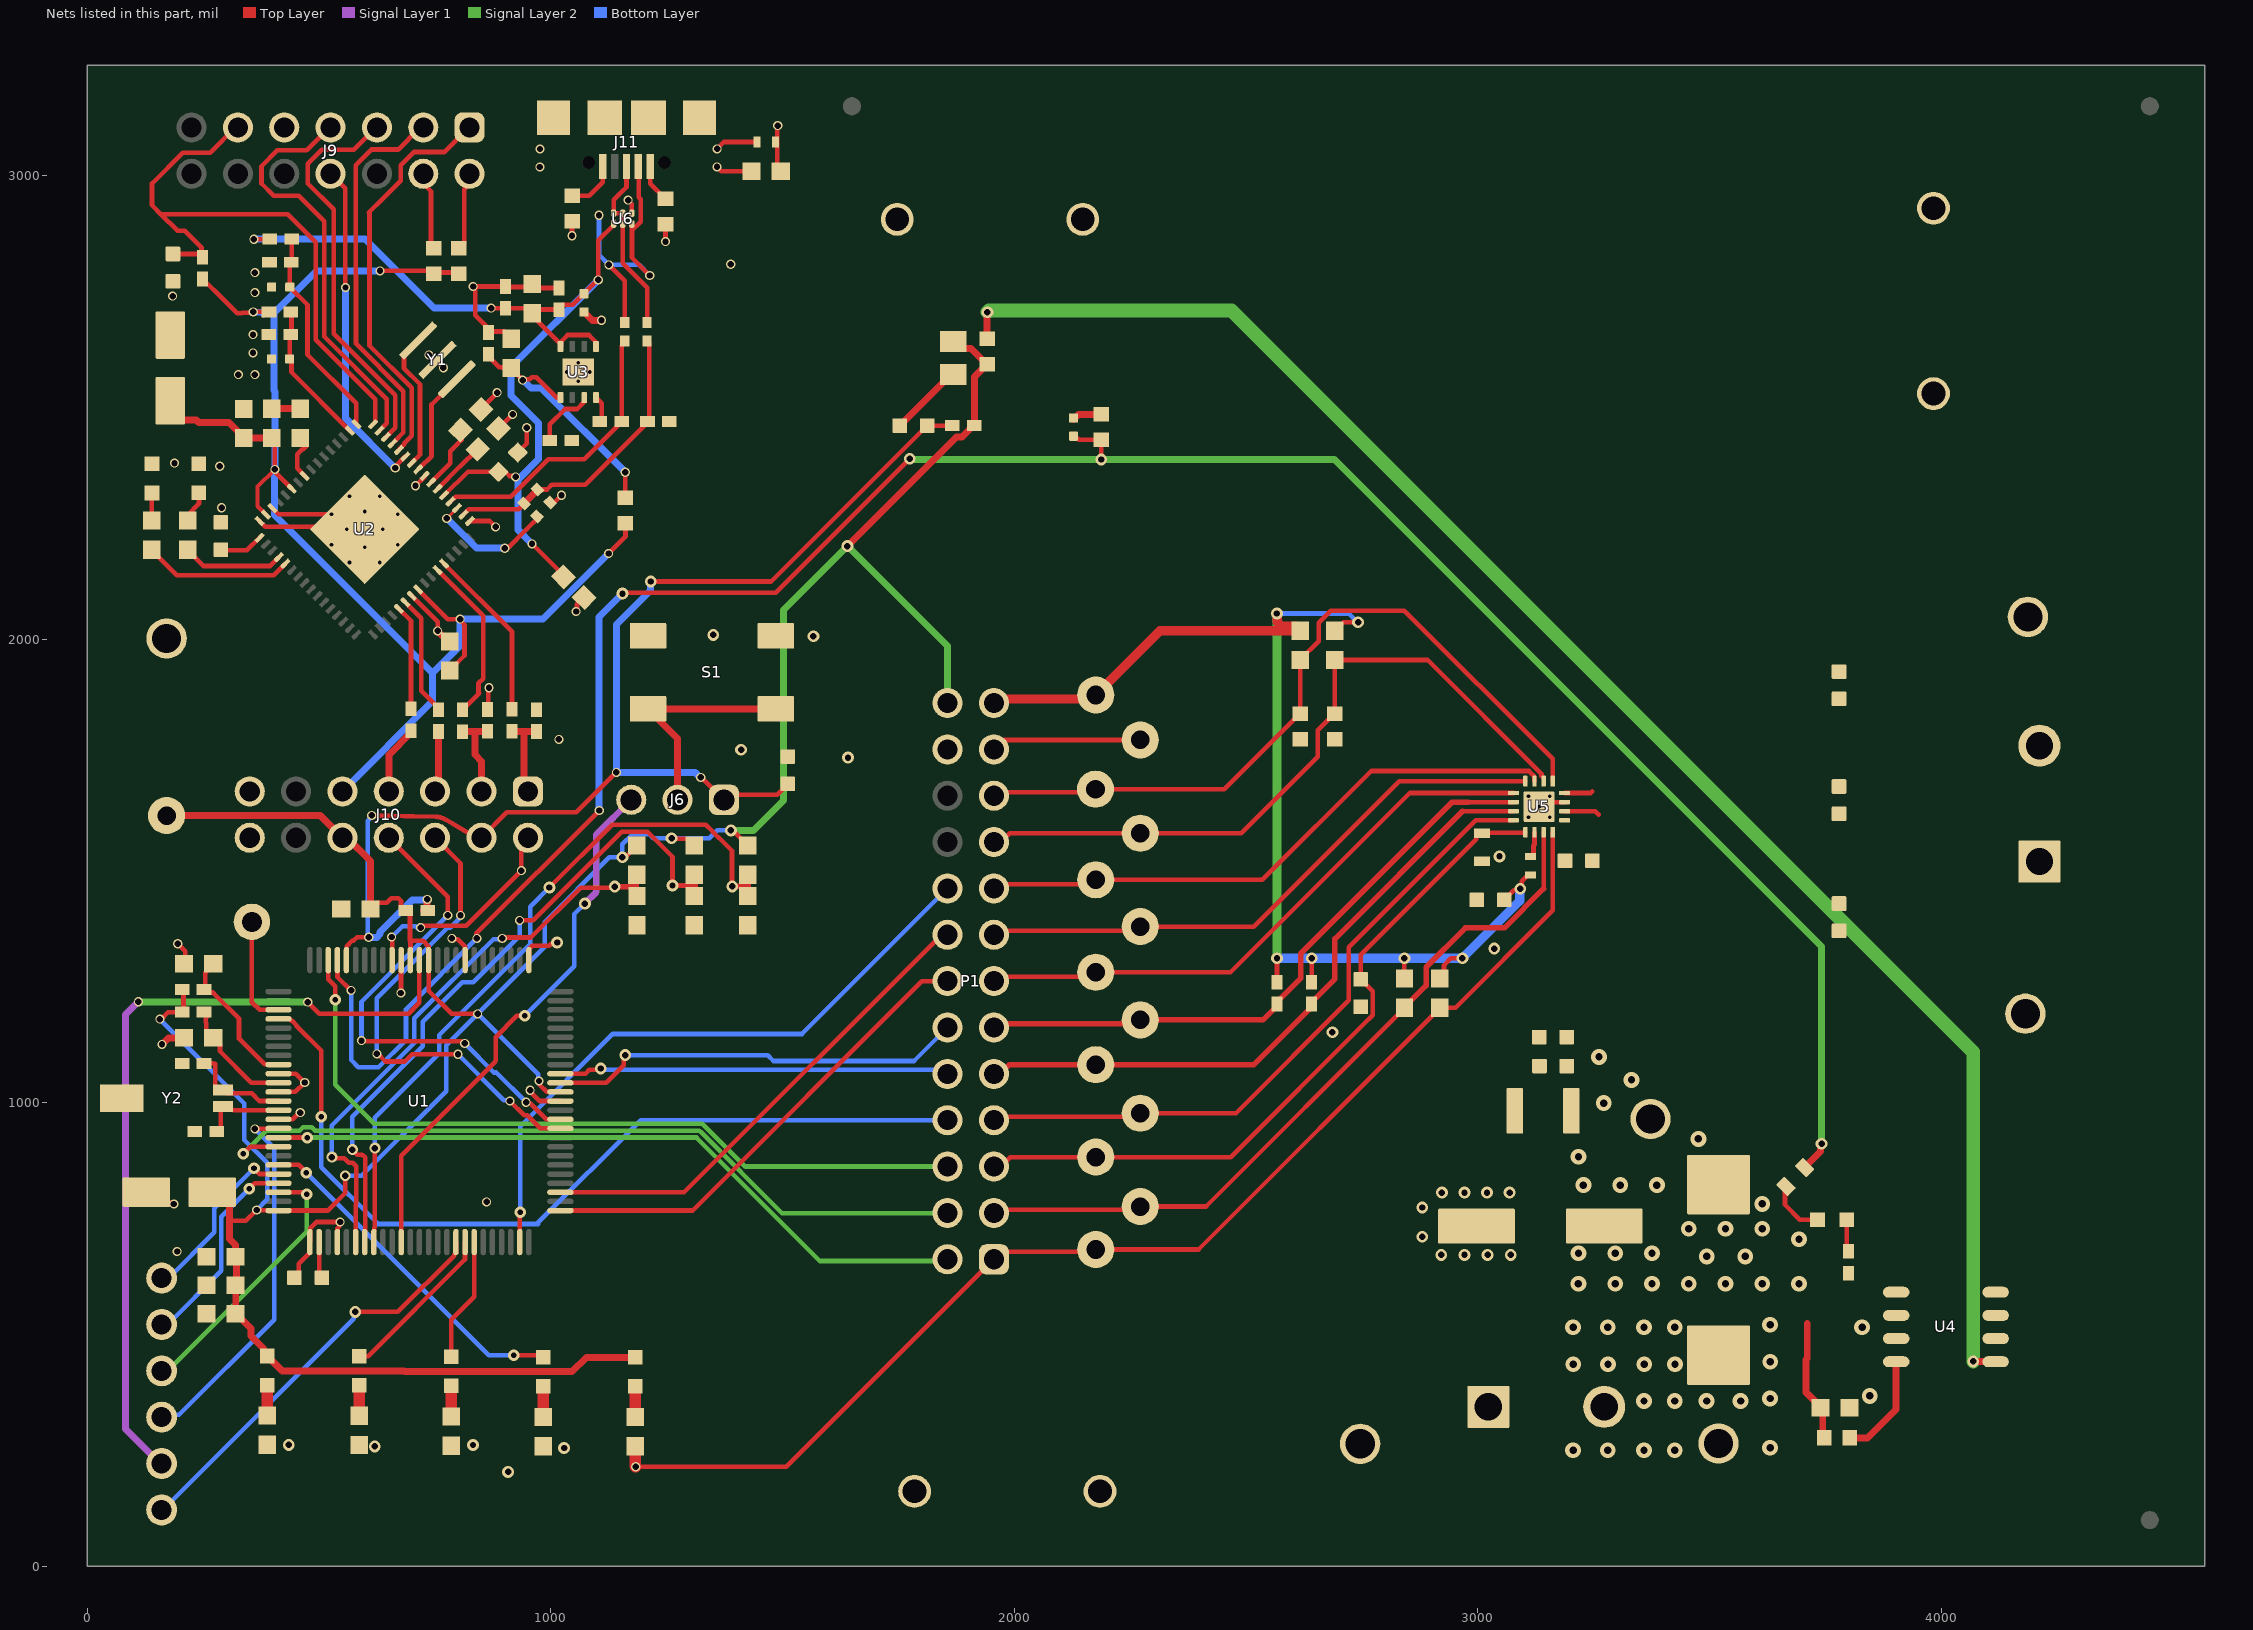
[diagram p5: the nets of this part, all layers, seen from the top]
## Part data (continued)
R43 R45 R47 R48: library part CMP-0025785-4, "RES, 330, 5%, 0.1 W, AEC-Q200 Grade 0, 0603", Manufacturer=Vishay-Dale, Power_W=100mW, Supplier Part Number 1=541-330GCT-ND, TempCo="200 ppm/C", Tolerance_%=5%, Value2=0.1W, Value_Code=330R, ValueDisplayed=330
R55 R60: library part CMP-0026728-1, "RES, 220 k, 1%, 0.0625 W, 0402", Manufacturer="Yageo America", Power_W=62.5mW, Supplier Part Number 1=311-220KLRCT-ND, TempCo="100 ppm/C", Tolerance_%=1%, Value2=0.0625W, Value_Code=220k
R56: library part CMP-0026190-2, "RES, 240 k, 1%, 0.063 W, AEC-Q200 Grade 0, 0402", Manufacturer=Vishay-Dale, Power_W=63mW, Supplier Part Number 1=541-240KLCT-ND, TempCo="100 ppm/C", Tolerance_%=1%, Value2=0.063W, Value_Code=240k
R58: library part CMP-0025924-5, "RES, 470, 5%, 0.1 W, 0603", Manufacturer=Yageo, Power_W=100mW, Supplier Part Number 1=311-470GRCT-ND, TempCo="100 ppm/C", Tolerance_%=5%, Value2=0.1W, Value_Code=470R, ValueDisplayed=470
R61: library part CMP-0026021-3, "RES, 150 k, 1%, 0.063 W, AEC-Q200 Grade 0, 0402", Manufacturer=Vishay-Dale, Power_W=63mW, Supplier Part Number 1=541-150KLCT-ND, TempCo="100 ppm/C", Tolerance_%=1%, Value2=0.063W, Value_Code=150k
R72 R75: library part CMP-0026888-3, "RES, 27, 5%, 0.063 W, AEC-Q200 Grade 0, 0402", Manufacturer=Vishay-Dale, Power_W=63mW, Supplier Part Number 1=541-27JCT-ND, TempCo="200 ppm/C", Tolerance_%=5%, Value2=0.063W, Value_Code=27R0, ValueDisplayed=27
R76: library part CMP-0026085-3, "RES, 1.40 k, 1%, 0.063 W, AEC-Q200 Grade 0, 0402", Manufacturer=Vishay-Dale, Power_W=63mW, Supplier Part Number 1=541-1.40KLCT-ND, TempCo="100 ppm/C", Tolerance_%=1%, Value2=0.063W, Value_Code=1k40, ValueDisplayed=1.40k
R77: library part CMP-0026859-2, "RES, 1.0 M, 5%, 0.063 W, AEC-Q200 Grade 0, 0402", Manufacturer=Vishay-Dale, Power_W=63mW, Supplier Part Number 1=541-1.0MJCT-ND, TempCo="200 ppm/C", Tolerance_%=5%, Value2=0.063W, Value_Code=1M00, ValueDisplayed=1.0M
R78: library part CMP-0026907-3, "RES, 33 k, 5%, 0.063 W, AEC-Q200 Grade 0, 0402", Manufacturer=Vishay-Dale, Power_W=63mW, Supplier Part Number 1=541-33KJCT-ND, TempCo="200 ppm/C", Tolerance_%=5%, Value2=0.063W, Value_Code=33k0, ValueDisplayed=33k
S1: library part CMP-0097347-1, "Tactile Switch SPST-NO Top Actuated Surface Mount", Coil Resistance_ohm=100mΩ, Contact Current Rating=50mA, Digikey Part Number=732-7022-1-ND, Manufacturer="Wurth Electronics", Mouser Part Number=710-430481025816, Operating Force=160gf, Operating Temperature Range="-40°C to +85°C"
SH-J1 SH-J2 SH-J3 SH-J4 SH-J5 SH-J6 SH-J7 SH-J8 SH-J9 SH-J10 SH-J11 SH-J12 SH-J19 SH-J29 SH-J31 SH-J32 SH-J33 SH-J34 SH-J36: library part CMP-0003761-2, "Shunt, 2.54mm, Gold, Black", Manufacturer="Wurth Elektronik", Supplier Part Number 1=732-2678-ND
TP1 TP2 TP3 TP4 TP5 TP6 TP7: library part CMP-0003719-1, "Testpoint", Manufacturer="Texas Instruments"
TP8 TP10: library part CMP-0055149-2, "Test Point, Multipurpose, White, TH", Color=White, Manufacturer="Keystone Electronics", Supplier Part Number 1=36-5012-ND
TP16 TP17 TP60: library part CMP-0075110-1, "1mm Uninsulated Shorting Plug, 10.16mm spacing, TH", Manufacturer=Harwin, PartNumber=D3082-05, Supplier Part Number 1=952-1873-ND
TP26: library part CMP-0055140-2, "Test Point, Miniature, Orange, TH", Color=Orange, Manufacturer="Keystone Electronics", Supplier Part Number 1=36-5003-ND
TP28 TP29 TP30 TP31 TP32 TP33 TP34 TP35 TP36 TP37 TP38 TP39 TP40: library part CMP-0055139-2, "Test Point, Miniature, White, TH", Color=White, Manufacturer="Keystone Electronics", Supplier Part Number 1=36-5002-ND
U1: library part CMP-0038879-1, "20 MHz Mixed Signal Microcontroller with 256 KB Flash, 18432 B SRAM and 74 GPIOs, -40 to 85 degC, 100-pin QFP (PZ), Green (RoHS & no Sb/Br)", Frequency(MHz)=20, Manufacturer="Texas Instruments", Temp Sensor=Yes
U2: library part CMP-0039269-4, "16-Bit Ultra-Low-Power Microcontroller, 128KB Flash, 8KB RAM, USB, 12Bit ADC, 2 USCIs, 32Bit HW MPY, RGC0064B (VQFN-64)", Alternate Manufacturer="Texas Instruments", Alternate PartNumber=MSP430F5528IRGCR, Frequency(MHz)=25, Operating Temperature Range="-40 to 85 C", Rating=Catalog, Temp Sensor=Yes
U3: library part CMP-0036328-3, "500mA, Adjustable, Low Quiescent Current, Low-Noise, High-PSRR, Single-Output LDO Regulator, DRB0008A (VSON-8)", Manufacturer="Texas Instruments", Operating Temperature Range="-40 to 125 C", Rating=Catalog
U4: library part CMP-0070570-1, "Ultra-Low Quiescent Current Voltage Regulator, 8-pin Narrow SOIC, Pb-Free", Manufacturer="Texas Instruments", PackageTopMarking=NSZXTT*LM903*6M-3, PowerWise=N
U5: library part CMP-0097573-1, "2-A Brushed DC Motor Driver with Stall Detection, Ripple Counting and Speed Regulation", Manufacturer="Texas Instruments", Max Supply Voltage=11V, Min Supply Voltage=1.65V, Operating Temperature Range="-40°C to +150°C", Switching Frequency=200kHz
U6: library part CMP-0043099-3, "Low-Capacitance 2-Channel +/-15kV ESD Protection Array for High-Speed Data Interfaces, DRY0006A (USON-6)", Breakdown Voltage(Min)(V)=11, IO Capacitance(Typ)(pF)=1.5, IO Leakage Current(nA)=1, Manufacturer="Texas Instruments", Operating Temperature Range="-40 to 85 C", Rating=Catalog
VM VSUP: library part CMP-0055147-2, "Test Point, Multipurpose, Red, TH", Color=Red, Manufacturer="Keystone Electronics", PartNumber=36-5010-ND
Y1: library part CMP-0085483-1, "Oscillator, 4 MHz, 700 ppm, 39 pF, SMD", Frequency_Fixed=4MHz, Frequency Tolerance="700 ppm", Load Capacitance="39 pF", Manufacturer=MuRata
Y2: library part CMP-0004566-4, "Crystal, 32.768 kHz, 12.5pF, SMD", Frequency Tolerance="20 ppm", Frequency_Fixed=32.768kHz, Load Capacitance="12.5 pF", Manufacturer="Micro Crystal AG", Supplier Part Number 1=94M8466
ZZ1: library part CMP-0077236-1
ZZ2: library part CMP-0077237-1
ZZ3: library part CMP-0077238-1
ZZ4: library part CMP-0003616-3

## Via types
v1: diameter 19.68, hole 13.78, Top Layer to Bottom Layer, tented both sides, 92 vias
v2: diameter 25.59, hole 13.78, Top Layer to Bottom Layer, tented both sides, 49 vias
v3: diameter 34, hole 16, Top Layer to Bottom Layer, tented both sides, 47 vias
v4: diameter 19.68, hole 7.87, Top Layer to Bottom Layer, 16 vias
v5: diameter 25/25/25/25 (per signal layer), hole 12, Top Layer to Bottom Layer, 11 vias
v6: diameter 19.68, hole 7.87, Top Layer to Bottom Layer, tented both sides, 5 vias
v7: diameter 23.62, hole 13.78, Top Layer to Bottom Layer, tented both sides, 4 vias

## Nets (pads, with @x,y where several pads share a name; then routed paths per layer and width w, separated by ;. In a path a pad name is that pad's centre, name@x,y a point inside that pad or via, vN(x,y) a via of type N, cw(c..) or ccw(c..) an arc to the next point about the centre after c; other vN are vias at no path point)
A0: P1.19 R8.2 R13.1 TP37.1 U5.10 | length 1558
  Top Layer w10: P1.19@1956.3,1562.7 1971.17,1562.7 1990.21,1581.73 TP37.1@2272.18,1581.73 2490.28,1581.73 2655.14,1746.6 2655.14,1803.69 2691.02,1839.56 R8.2@2692,1839.56 R13.1@2692,1955.5 2892.32,1955.5 3137.61,1710.21 3137.61,1705.39 U5.10@3142.02,1700.98
A1: P1.21 R10.2 R14.1 TP38.1 U5.9 | length 1643.1
  Top Layer w10: P1.21@1956.3,1662.7 1963.39,1669.79 2168.47,1669.79 TP38.1@2175.57,1676.89 2453.35,1676.89 2616.02,1839.56 R10.2@2617,1839.56 R14.1@2617,1955.5 2617,1956.49 2656.84,1996.33 2656.84,2035.86 2682.98,2062 2842,2062 3161.98,1742.02 U5.9@3161.98,1694.17
DRV_3V3: C2.2 P1.25 R1.1 R5.1 R6.1 R7.1 R13.2 R14.2 R24.1 TP40.1 | length 2699.4
  Top Layer w10: R6.1@2567,1260.62 v2(2567,1312) ; R7.1@2642,1260.62 v2(2642,1312) ; R13.2@2692,2018.5 2692,2019.48 2705.7,2033.18 2706.69,2033.18 2710.5,2037 v2(2742,2037) ; R1.1@2842,1268.5 v2(2842,1312) ; R24.1@2918.44,1268.5 2927.32,1277.38 2927.32,1297.32 2942,1312 v2(2967,1312) ; C2.2@3057.07,1437.94 3078.14,1459.02 3089.02,1459.02 3094.98,1464.98 3094.98,1477.77 3109.21,1492 R5.1@3113.71,1492
  Top Layer w20: P1.25@1956.3,1862.7 1964.9,1871.3 2167.53,1871.3 2314.72,2018.5 2577.33,2018.5 2608.3,2018.5 R14.2@2617,2018.5 2617,2019.48 2608.3,2028.18 2577.33,2028.18 2567.86,2037.65 2567.86,2054.72 v2(2566.79,2055.79)
  Signal Layer 2 w20: v2(2566.79,2055.79) 2566.9,2055.68 2566.9,1312.1 v2(2567,1312)
  Bottom Layer w10: v2(2566.79,2055.79) 2721.48,2055.79 2740.26,2037 v2(2742,2037)
  Bottom Layer w20: v2(2567,1312) v2(2967,1312) 3090.93,1435.93 3090.93,1460.93 v2(3092,1462)
EZFET_AVBUS: C24.2 R56.1 R61.2 U2.1 | length 460.2
  Top Layer w10: R56.1@441.36,2863.26 441.36,2813.97 437.4,2810.02 C24.2@437.4,2759.93 475.64,2721.68 475.64,2614.32 580.83,2509.13 U2.1@580.83,2464.1
EZFET_AVCC2ADC: C22.2 R55.1 R60.2 U2.2 | length 312.5
  Top Layer w10: R55.1@439.69,2706.57 441.02,2705.24 441.02,2658.99 436.96,2654.94 C22.2@436.96,2605.12 441.02,2601.07 441.02,2576.07 U2.2@566.91,2450.18
EZFET_D_N: C42.1 R72.2 U2.52 | length 613.9
  Top Layer w10: U2.52@784.05,2297.07 794.99,2308 914.1,2308 994.59,2388.49 1072.35,2388.49 C42.1@1153.52,2469.66 1153.52,2633.53 R72.2@1159.94,2639.95
EZFET_D_P: C43.1 R75.2 R76.1 R77.2 U2.50 | length 662.5
  Top Layer w10: U2.50@811.89,2269.23 823.67,2281 931,2281 R76.1@943,2293 ; R77.2@971.43,2323.27 992.2,2323.27 1002.57,2333.64 1074.64,2333.64 C43.1@1212,2471 ; R75.2@1208,2645 1213.01,2639.99 C43.1@1213.01,2469.66
  Top Layer w15: R76.1@942.97,2293.25 971,2321.28 R77.2@971,2324
EZFET_LED0: R58.1 U2.20 | length 219.7
  Top Layer w10: R58.1@217.05,2193.48 217.05,2192.5 251.15,2158.4 394.84,2158.4 U2.20@413.8,2177.36
EZFET_LED1: R59.1 U2.21 | length 322.2
  Top Layer w10: R59.1@139.47,2193.44 139.47,2192.46 193.82,2138.1 402.38,2138.1 U2.21@427.72,2163.44
EZFET_PUR: R76.2 U2.51 | length 282.9
  Top Layer w6: v1(776.09,2260.93) 797.97,2282.81 U2.51@797.97,2283.34
  Top Layer w10: v1(901,2196.64) 907.6,2196.64 949,2238.03 R76.2@973.59,2262.62
  Bottom Layer w15: v1(776.09,2260.93) 840.39,2196.64 v1(901,2196.64)
EZFET_RST: C23.2 J9.11 R57.1 U2.64 | length 1315.2
  Top Layer w10: C23.2@185.39,2831.42 242.7,2831.42 R57.1@249.39,2824.73 246.8,2827.32 246.8,2845.48 210.88,2881.4 195.25,2881.4 159.33,2917.31 ; J9.11@325.43,3104.4 320.31,3104.4 265.67,3049.76 206.64,3049.76 140.19,2983.31 140.19,2936.45 159.33,2917.31 ; U2.64@621.64,2469.11 621.64,2517.86 493.52,2645.99 493.52,2856.87 433.07,2917.31 159.33,2917.31
EZFET_TCK: J9.7 U2.63 | length 899.5
  Top Layer w10: J9.7@521.76,3102.24 474.32,3054.8 410.18,3054.8 376.4,3021.03 376.4,2983.46 402.97,2956.89 456.38,2956.89 511.39,2901.88 511.39,2653.39 646.78,2518 646.78,2466.22 U2.63@630.94,2450.38
EZFET_TDI: J9.3 U2.61 | length 820.7
  Top Layer w10: U2.61@663.5,2427.26 682.53,2446.29 682.53,2535.19 580.33,2637.39 580.33,2785.81 580.07,2786.06 580.07,3023.19 613.53,3056.65 671.2,3056.65 716.8,3102.24 J9.3@721.76,3102.24
EZFET_TDO: J9.1 U2.60 | length 870.4
  Top Layer w10: U2.60@672.7,2408.62 684.58,2420.51 684.58,2423.06 700.4,2438.89 700.4,2542.6 609.28,2633.72 609.28,2920.05 608.32,2921.01 638.16,2950.84 676.4,2989.09 676.4,3023.01 704.65,3051.26 770.77,3051.26 J9.1@821.76,3102.24
EZFET_TEST: J9.8 U2.59 | length 726
  Top Layer w10: J9.8@525.43,3004.4 557,2972.83 v1@557,2759 ; v1(664.79,2369.8) 664.79,2372.87 686.52,2394.6 U2.59@686.62,2394.7
  Bottom Layer w15: v1(557.61,2759) 557.61,2476.98 v1(664.79,2369.8)
EZFET_TMS: J9.5 U2.62 | length 852.8
  Top Layer w10: J9.5@621.76,3102.24 575.77,3056.26 506.42,3056.26 476.4,3026.23 476.4,2983.46 531.92,2927.94 531.92,2658.92 664.65,2526.19 664.65,2456.25 U2.62@644.86,2436.46
EZFET_UARTRXD: R66.1 U2.38 | length 254.2
  Top Layer w10: U2.38@691.43,2075.11 721.16,2045.38 721.16,1889.09 757.89,1852.36 R66.1@757.89,1848.42
EZFET_UARTTXD: R67.1 U2.37 | length 227
  Top Layer w10: U2.37@672.7,2066.2 698.91,2039.99 R67.1@698.91,1850
EZFET_USB_Shield: C47.1 J11.Shell R78.2 | length 181.9
  Top Layer w10: v1(1359,3019.41) 1368.38,3010.03 C47.1@1445,3010.03 ; v1(1359.15,3058.16) 1373.99,3073 R78.2@1445,3073
  other v1: 977,3019 977.15,3057.75
EZFET_V18: C28.1 U2.55 | length 140.3
  Top Layer w10: U2.55@742.29,2339.02 783.3,2379.94 783.3,2405.64 795,2417.34 807.89,2430.23 805.66,2432.46 C28.1@805.66,2451.21
EZFET_VBUS: C20.2 C21.1 C35.1 C36.1 C37.1 C48.2 L1.2 R56.2 U2.53 U3.5 U3.8 U6.1 | length 2228.6
  Top Layer w10: v1(359.89,2863.28) R56.2@390.15,2863.28 ; U2.53@770.13,2311.18 821.98,2361.33 902.6,2361.33 911.44,2352.49 922.76,2352.49 v1(924.61,2350.63) ; v1(871.84,2714.63) C35.1@899.4,2714.63 ; C35.1@902.39,2713.98 949.8,2713.98 C36.1@960.11,2703.67 961.17,2704.74 C36.1@966.92,2704.74 ; v1(959.96,2206) C21.1@1033.59,2132.37 ; U3.8@1021.31,2631.89 1022.41,2632.99 1022.41,2642.38 1036.61,2656.57 1082.78,2656.57 1096.98,2642.38 1096.98,2632.99 U3.5@1098.08,2631.89 ; U3.8@1021.31,2637.6 973.81,2685.1 973.81,2697.85 C36.1@966.92,2704.74 ; U6.1@1136.03,2896.75 1135.13,2895.85 1135.13,2892.89 1102.83,2860.6 v1(1102.83,2775.6) 1101.91,2775.6 1047.87,2721.56 1025.06,2721.56 1018.24,2714.75 C37.1@1018.24,2710.81 1017.51,2711.55 973.73,2711.55 C36.1@966.92,2704.74 ; v1(1247.92,2858.14) L1.2@1247.92,2891.25
  Bottom Layer w15: v1(359.89,2863.28) 599.38,2863.28 748.03,2714.63 v1(871.84,2714.63) ; v1(924.61,2350.63) v1@930.19,2345.05 ; v1(959.96,2206) 930.19,2235.77 v1@930.19,2345.05 ; v1(1102.83,2775.6) 914.39,2587.16 914.39,2526.54 973.9,2467.04 973.9,2388.76 v1@930.19,2345.05
EZFET_VCC: C31.2 C32.1 C33.1 C34.1 J10.9 R55.2 R57.2 R62.2 R63.2 R68.1 U2.11 U2.15 U2.40 | length 3248.3
  Top Layer w9: U2.15@385.96,2269.23 368.06,2287.12 368.06,2329.67 v1(405.25,2366.86)
  Top Layer w10: R57.2@249.39,2777.49 294.5,2732.38 295.28,2732.38 323.79,2703.87 333.79,2703.87 334.63,2704.72 356.73,2704.72 v1(358.58,2706.57) R55.2@388.5,2706.57 ; v1(405.25,2366.86) C32.1@405.25,2434.61 ; v1@407.1,2359.44 U2.11@441.63,2324.9 ; v1(632,2795) 741.76,2795 R62.2@748.08,2788.68 748.65,2788.11 753.71,2788.11 757.13,2791.53 798.74,2791.53 R63.2@801.84,2788.43 ; U2.40@719.27,2102.94 778.47,2043.74 v1(804.86,2043.74) 804.86,2041.12 814.29,2031.69 814.29,1965.19 C34.1@785.67,1936.56 ; v1@1125.28,2185.53 1161.5,2221.74 R68.1@1161.5,2250.8
  Top Layer w15: C31.2@179.54,2514.77 179.54,2496.97 203.54,2472.97 235.64,2472.97 241.04,2467.57 305.95,2467.57 338.36,2435.16 C33.1@338.36,2434.17 338.58,2434.39 398.29,2434.39 C32.1@398.51,2434.61
  Bottom Layer w15: v1(358.58,2706.57) 359.48,2705.68 377.62,2705.68 380.91,2702.38 382.4,2703.87 403.61,2703.87 ; v1@404.19,2366.86 404.19,2268.59 745.69,1927.09 ; v1(405.25,2366.86) 405.25,2535.18 403.61,2536.82 403.61,2703.87 ; J10.9@551,1672.02 745.69,1866.71 745.69,1927.09 ; v1(632,2795) 494.74,2795 403.61,2703.87 ; v1(1125.28,2185.24) 983.78,2043.74 v1(804.86,2043.74) 804.86,1986.26 745.69,1927.09
EZFET_Vcore: C29.2 U2.17 | length 94.9
  Top Layer w10: C29.2@288.85,2193.18 289.95,2192.07 345,2192.07 U2.17@372.04,2219.12
EZFET_VREF: C25.1 U2.9 | length 104.8
  Top Layer w10: C25.1@459.95,2434.61 473.65,2420.91 473.65,2418 474.35,2417.3 466.81,2409.76 464.01,2409.76 453.42,2399.17 453.42,2368.8 U2.9@469.47,2352.74
EZFET_VUSB: C30.1 U2.54 | length 121.4
  Top Layer w10: U2.54@756.21,2325.1 804.07,2372.87 C30.1@842.84,2410.16
EZFET_XT2IN: U2.57 Y1.1 | length 222.2
  Top Layer w10: U2.57@719.27,2371.48 743.21,2395.42 743.21,2506.62 Y1.1@797.78,2561.19
EZFET_XT2OUT: U2.58 Y1.3 | length 298.5
  Top Layer w10: U2.58@700.54,2380.58 700.54,2380.97 718.28,2398.71 718.28,2550 683.64,2584.64 683.64,2614.08 Y1.3@714.26,2644.7
GND: C1.1 C2.1 C3.1 C4.1 C6.2 C7.2 C8.1 C15.2 C20.1 C21.2 C22.1 C23.1 C24.1 C25.2 C26.1 C27.1 C28.2 C29.1 C30.2 C31.1 C32.2 C33.2 C34.2 C35.2 C36.2 C37.2 C38.2 C39.2 C40.2 C41.1 C42.2 C43.2 C44.1 C45.2 C46.1 C47.2 C48.1 C49.1 C50.2 C51.1 C52.2 C53.2 C54.2 C55.2 C56.1 C57.1 C58.1 C59.1 C60.1 D1.1 D2.1 GND.1 J8.1 J9.9 J10.13 J10.14 L2.2 P1.23 P1.24 R2.2 R8.1 R10.1 R11.1 R35.1 R42.1 R43.1 R45.1 R47.1 R51.2 R52.2 R53.2 R60.1 R61.1 R77.1 R78.1 S1.3 S1.4 TP16.1 TP16.2 TP17.1 TP17.2 TP24.1 TP39.1 TP60.1 TP60.2 U1.10 U1.12 U1.15 U1.26 U1.29 U1.63 U1.76 U1.83 U1.90 U2.14 U2.16 U2.39 U2.49 U2.56 U2.65 U3.4 U3.9 U4.2 U4.3 U4.4 U4.5 U4.6 U4.7 U5.7 U5.17 U6.4 Y1.2 Y2.3 | length 3062.4
  Top Layer w10: v1(195.63,1343.31) 212.06,1326.88 C15.2@212.06,1300.54 ; U2.16@372.04,2255.31 384.35,2243 499,2243 U2.65@526,2270 ; U2.14@399.88,2283.15 412,2271.02 413,2270 U2.65@526,2270 ; U1.15@413.02,964.63 413.37,964.98 443.36,964.98 457.38,979 v1(460,979) ; U1.12@413.02,1023.69 449.48,1023.69 v1(469.73,1043.94) 450.62,1063.06 U1.10@413.02,1063.06 ; C49.1@447.41,622.9 456.6,632.09 456.6,652.89 480.35,676.64 480.35,699.27 481.28,700.21 481.28,729.72 494.56,743 v1(546,743) 544.15,741.15 544.15,733.53 540.34,729.72 540.34,700.21 U1.29@539.99,699.87 ; U2.65@528,2270 U2.65@526,2270 ; C54.2@556.45,1412.89 C54.2@556.45,1418.17 ; v1(677,1237) 677.44,1237.44 677.44,1307.79 U1.90@677.79,1308.13 ; U2.39@700.54,2093.84 756.44,2037.94 v1(756.44,2018.19) ; v1(708.63,2331.36) 728.37,2351.11 U2.56@728.37,2352.94 ; v1(737.32,2613.62) 752.01,2598.93 755.94,2598.93 v1(768.82,2586.06) ; v1(787,1355) 788.85,1353.15 800.08,1353.15 815.24,1337.99 815.24,1308.48 U1.83@815.58,1308.13 ; U2.49@825.81,2255.31 868.77,2255.31 v1(881.43,2242.66) ; v1(832.84,2761.19) C35.2@902.39,2761.23 C35.2@902.39,2761.23 903.58,2760.04 958.86,2760.04 958.86,2765.42 C36.2@960.11,2766.66 960.11,2758.79 960.85,2758.05 C37.2@1018.24,2758.05 ; v1@837.32,2759.95 v1@837.32,2761.19 ; v1@837.35,2759.95 837.35,2699.48 865.88,2670.95 C40.2@865.88,2662.09 ; C28.2@844.64,2490.19 844.64,2492.14 v1(884.79,2532.29) ; C27.1@863.56,1848.62 865.62,1850.68 865.62,1894.09 v1(867.13,1895.6) ; C40.2@868.09,2664.3 900.06,2664.3 914.83,2649.54 C38.2@914.83,2648.55 ; C30.2@881.84,2449.12 v1(918.12,2485.39) ; C20.1@929.16,2403.09 948.69,2422.62 v1(948.69,2456.59) ; U1.76@953.38,1308.13 953.72,1308.48 953.72,1332.56 960.14,1338.98 997.36,1338.98 1001.4,1343.02 1011.02,1343.02 v2(1014,1346) ; v1(955.9,1027.44) 955.9,1024.82 961.73,1018.98 961.73,1018.89 976.62,1004 U1.63@1021.29,1004 ; R77.1@1002.05,2292.65 1005.22,2292.65 v1(1023.49,2310.92) ; v1(1046.16,2870.62) 1046.16,2897.07 L2.2@1046.9,2897.81 ; v1(1055,2060) 1056.85,2061.85 1056.85,2075.9 1076,2095.04 C21.2@1076,2096 ; U3.4@1098.08,2521.65 1110,2509.73 C42.2@1110,2469 ; v1(1167.24,2947.46) 1175.4,2939.29 U6.4@1175.4,2919.39 ; C47.2@1488.62,3010.03 1488.62,3106.82 v1(1490,3108.19) ; P1.23@1956.3,1762.7 1976.65,1783.05 TP39.1@2272.18,1783.05 ; v6(3132.46,1639.05) 3142.3,1648.89 U5.7@3187.57,1648.89
  Top Layer w15: C51.1@128.11,807.41 152.11,783.41 184.44,783.41 185.99,781.86 v1(187.25,781.86) ; v1(161.75,1126.27) 175.73,1140.26 209,1140.26 C50.2@209.14,1140.4 ; C32.2@398.51,2497.6 C25.2@459.95,2497.6 ; v1(756.44,2018.19) 756.44,2017.96 C34.2@782.72,1991.68 ; C48.1@1072,2706.31 1089.99,2688.32 v1(1109.95,2688.32) ; C59.1@1760,2462 1760,2467.53 1847.7,2555.23 1847.7,2556.28 1865.72,2574.29 C7.2@1868.75,2574.29 ; C60.1@2128,2473.89 2139.11,2485 R35.1@2188,2485
  other v1: 194.42,679.39 862.07,786.49 1017.9,1784.11 290.25,2284.05 286.34,2373.53 188.74,2380.09 326.57,2571 362,2571 358.13,2618.01 358.13,2657.37 184.63,2740.37 362.07,2747.93 362.07,2791.24 1388.61,2809.27
  other v2: 908.31,203.92 1029.27,255.64 620.67,258.95 435.05,262.33 832.63,262.02 2921.51,672.26 2971.51,672.26 3021.51,672.26 3071.51,672.26 2880.51,711.26 2880.51,774.26 2922.92,806.53 2971.59,806.53 3020.25,806.53 3068.92,806.53 2686.5,1152.48 3035.64,1332.8 3047.22,1531.84 1641.56,1744.96 1410.99,1761.88 1566.98,2006.66 1350.86,2009.68
  other v3: 3845.95,367.95 3829.38,516
  other v4: 566.07,2165.67 631.77,2165.67 598.92,2198.52 527.38,2204.36 670.47,2204.36 560.23,2237.21 637.62,2237.21 527.38,2270.06 670.47,2270.06 598.92,2275.91 566.07,2308.76 631.77,2308.76 1059.69,2557.09 1035.09,2576.77 1084.3,2576.77 1059.69,2596.46
  other v6: 3109.62,1616.22 3155.29,1616.22 3109.62,1661.88 3155.29,1661.88
GUI_STATUS: D8.2 U1.44 | length 267.8
  Top Layer w10: D8.2@785.86,452.5 785.86,532.1 835.27,581.51 U1.44@835.27,699.87
ID1: R39.2 R51.1 U1.31 | length 1250.8
  Top Layer w10: v7(528.19,882.86) 530.8,880.25 554.48,880.25 564.2,870.53 573.5,870.53 580.72,863.32 580.72,782.59 579.36,781.24 U1.31@579.36,699.87 ; v1(895.72,1355) 897.57,1356.85 957.38,1356.85 1064.99,1464.47 1136.49,1464.47 v2(1138.5,1466.48) ; 1183.25,1466.48 1186.18,1469.41 ; R39.2@1186.18,1496.17 1186.18,1469.41 ; R51.1@1186.54,1442.29 1186.18,1442.65 1186.18,1469.41
  Top Layer w11.81: v2(1138.5,1466.48) 1183.25,1466.48
  Bottom Layer w10: v7(528.19,882.86) 528.19,951.35 706.11,1129.26 706.11,1182.38 876.88,1353.15 893.86,1353.15 v1(895.72,1355)
ID2: R40.2 R52.1 U1.32 | length 1462
  Top Layer w10: v7(572.28,899.17) 583.04,888.41 594.09,888.41 599.95,882.55 599.95,723.9 599.05,722.99 U1.32@599.05,699.87 ; v1(933.28,1393.72) 962.62,1393.72 1153.81,1584.91 1209.02,1584.91 1263,1530.93 v2(1263,1469) ; 1309.77,1469 1310,1469.23
  Top Layer w11.81: v2(1263,1469) 1309.77,1469
  Top Layer w15.75: R52.1@1310,1446.23 1310,1469.23 R40.2@1310,1492.23
  Bottom Layer w10: v7(572.28,899.17) 572.28,970.16 723.98,1121.86 723.98,1174.97 809.29,1260.28 833.13,1260.28 933.28,1360.44 v1(933.28,1393.72)
ID3: R41.2 R53.1 U1.33 | length 1552.2
  Top Layer w10: U1.33@618.73,699.87 618.73,722.99 619.64,723.9 619.64,730.28 620.86,731.5 v7(620.86,902.54) ; v2(997.35,1464.65) 1132.62,1599.91 1335.09,1599.91 1348.46,1586.54 1348.46,1585.86 1361.82,1572.5 1362.5,1572.5 1391.34,1543.66 1391.34,1467.66 v2(1392,1467) ; 1422.77,1467 1425,1469.23
  Top Layer w11.81: v2(1392,1467) 1422.77,1467
  Top Layer w15.75: R53.1@1425,1446.23 1425,1469.23 R41.2@1425,1492.23
  Bottom Layer w10: v7(620.86,902.54) 620.86,968.03 759.73,1106.9 759.73,1146.47 955.99,1342.74 955.99,1423.29 v2(997.35,1464.65)
IN1: P1.13 TP34.1 U5.13 | length 1289.2
  Top Layer w10: P1.13@1956.3,1262.7 1965.88,1272.28 2166.6,1272.28 TP34.1@2176.18,1281.86 2466.75,1281.86 2853.47,1668.58 U5.13@3077.34,1668.58
IN2: P1.15 TP35.1 U5.12 | length 1283.9
  Top Layer w10: P1.15@1956.3,1362.7 1965.16,1371.56 2263.32,1371.56 TP35.1@2272.18,1380.42 2516.81,1380.42 2830.56,1694.17 U5.12@3102.93,1694.17
IPROPI: C3.2 P1.5 R2.1 TP30.1 U5.1 | length 1563.5
  Top Layer w10: P1.5@1956.3,862.7 1971.17,862.7 1991.61,883.14 TP30.1@2176.18,883.14 2467.03,883.14 2765.62,1181.72 2766.52,1181.72 2773.57,1188.78 2773.57,1240.78 C3.2@2747.83,1266.53 2747.83,1319.89 2996.98,1569.05 2996.98,1576.55 3001.2,1580.76 3008.7,1580.76 3010.67,1582.74 3102.65,1582.74 3102.93,1583.01 U5.1@3102.93,1583.93
MCU_3V3: C7.1 C46.2 C51.2 C52.1 C53.1 C54.1 D5.2 D11.2 J10.10 P1.26 R4.1 R9.2 R18.1 R19.2 R37.1 R39.1 R40.1 R41.1 TP26.1 U1.25 U1.64 U1.87 U1.89 | length 6698.4
  Top Layer w10: v1(157.14,1180.88) 159.76,1180.88 174.6,1195.71 R37.1@205.03,1195.71 206.63,1195.71 208.06,1197.14 208.06,1244.72 R9.2@207.75,1245.03 ; 309.79,745.47 342.47,745.47 v1(366,769) 366.87,768.13 412.68,768.13 U1.25@413.02,767.78 519.08,767.78 556.99,805.7 v7(556.99,842.87) ; C54.1@611.57,1418.17 625.27,1431.87 646.25,1431.87 655.96,1441.58 671.44,1441.58 677.3,1435.72 677.3,1415.3 686.78,1415.3 R18.1@687.36,1414.72 690.05,1414.72 696.86,1407.91 696.86,1349.55 ; U1.89@697.47,1308.13 697.82,1308.48 697.82,1346.54 700.83,1349.55 724.94,1349.55 736.5,1337.99 736.5,1307.64 736.84,1307.3 736.84,1241.5 786.39,1191.95 v1(842.61,1191.95) ; v1(975.03,1047.28) 976.88,1045.43 976.88,1038.58 991.43,1024.03 1020.94,1024.03 U1.64@1021.29,1023.69 ; v2(1155,1530) 1157.98,1532.98 1164.92,1532.98 1183.23,1551.29 R39.1@1186.18,1551.29 ; v2(1261,1571) 1262.09,1569.91 1296.3,1569.91 1306,1560.21 R40.1@1306,1554 ; v2(1389,1588) 1393.21,1588 1425,1556.21 R41.1@1425,1555.23
  Top Layer w15: TP26.1@154.44,1619.87 TP26.1@171.7,1619.87 503.14,1619.87 J10.10@551,1572.02 561.27,1572.02 611.57,1521.72 C54.1@611.57,1418.17 ; C51.2@269.84,807.41 283.6,807.41 307.6,783.41 307.6,706.31 320.36,693.55 320.36,668.08 C53.1@320.52,667.92 322.23,666.21 322.23,608.02 C52.1@320.52,606.31 320.79,606.04 C46.2@320.79,545.23 ; C46.2@320.52,545.23 C46.2@320.79,545.23 ; D11.2@1182.94,451.23 1077.02,451.23 1046.16,420.37 734.28,420.37 734.02,420.63 684.89,420.63 683.89,421.63 421.14,421.63 D5.2@388.79,453.97 380.54,462.22 380.54,470.6 353.62,497.52 353.62,513.11 321.5,545.23 C46.2@320.79,545.23 ; v2(1640.26,2201.3) 1875.79,2436.83 1887.84,2436.83 1912.16,2461.14 R19.2@1914.16,2461.14 ; C7.1@1868.75,2639.41 1881.01,2627.14 1907.32,2627.14 1941.44,2593.01 1941.44,2592.46 1940.03,2592.46 1914.16,2566.59 R19.2@1914.16,2465.45
  Signal Layer 2 w15: v2(1389,1588) 1438,1588 1502.78,1652.78 1502.78,2063.82 v2@1639,2200.04 ; v2(1640.26,2201.3) 1856.3,1985.26 P1.26@1856.3,1862.7
  Bottom Layer w10: v1(157.14,1180.88) 339.28,998.74 339.28,919.94 388.72,870.51 388.72,791.72 v1(366,769) ; v7(556.99,842.87) 592.04,842.87 774.73,1025.57 774.73,1124.07 v1(842.61,1191.95) ; v1(975.03,1047.28) 973.18,1049.14 973.18,1061.39 v1(842.61,1191.95) ; v2(1389,1588) 1359.74,1588 1342.74,1571 1221.44,1571 1212.37,1580.07 1177.03,1580.07 1155,1558.04 v2(1155,1530) 1126.96,1530 987.16,1390.2 987.16,1336.5 v1(842.61,1191.95)
MCU_STATUS: D6.2 U1.43 | length 352.2
  Top Layer w10: D6.2@587.33,453.5 606.62,453.5 815.24,662.11 815.24,699.52 U1.43@815.58,699.87
MCU_UARTRXD: J10.8 U1.61 | length 1068.3
  Top Layer w10: v1(592.11,1134.24) 593,1133.34 807.26,1133.34 812.1,1128.5 v1(814.72,1128.5) ; J10.8@651,1572.02 778.18,1444.84 v1(778.18,1404.63) ; v1(947.2,1001.29) 949.06,999.44 955.91,999.44 990.37,964.98 1020.94,964.98 U1.61@1021.29,964.63
  Bottom Layer w10: v1(592.11,1134.24) 592.11,1218.55 778,1404.45 v1@778,1406 ; v1(814.72,1128.5) 877.67,1065.55 882.95,1065.55 v1(947.2,1001.29)
MCU_UARTTXD: J10.6 U1.60 | length 1040.5
  Top Layer w10: v1(625.22,1105.78) 627.5,1105.78 643.93,1089.35 685.45,1089.35 701.1,1105 v1(800.32,1105) ; J10.6@751,1572.02 805.74,1517.28 v1(805.74,1404.63) ; v1(912.18,1004.18) 943.21,973.16 949.55,973.16 977.75,944.96 U1.60@1021.28,944.96
  Bottom Layer w10: v1(625.22,1105.78) 625.22,1225.35 777.59,1377.72 783.39,1377.72 803.89,1398.21 803.89,1400.15 v1@806,1402.27 ; v1(800.32,1105) 899.28,1006.04 910.33,1006.04 v1(912.18,1004.18)
MSP_IN1: P1.14 U1.51 | length 1040
  Top Layer w10: U1.51@1021.29,767.78 1306.09,767.78 1801.01,1262.7 P1.14@1856.3,1262.7
MSP_IN2: P1.16 U1.53 | length 1065.1
  Top Layer w10: U1.53@1021.29,807.15 1287.91,807.15 1843.45,1362.7 P1.16@1856.3,1362.7
MSP_IPROPI: P1.6 U1.98 | length 1669.1
  Top Layer w10: U1.98@520.31,1308.13 520.31,1266.78 535.67,1251.42 v5(535.67,1222.23)
  Signal Layer 2 w10: v5(535.67,1222.23) 535.67,1039.1 619.51,955.26 1327.14,955.26 1419.71,862.7 P1.6@1856.3,862.7
MSP_nFAULT: P1.2 U1.17 | length 1556.1
  Top Layer w10: U1.17@413.02,925.26 v5(475.13,925.26) v5@475.87,925.99
  Signal Layer 2 w10: v5(475.13,925.26) 1314.72,925.26 1580.98,659 1852.6,659 P1.2@1856.3,662.7
MSP_nSLEEP: P1.18 U1.49 | length 1384.1
  Top Layer w10: U1.49@933.69,699.87 933.69,763.64 v5(934.55,764.5)
  Bottom Layer w10: v5(934.55,764.5) 934.55,949.09 1134.22,1148.76 1542.36,1148.76 P1.18@1856.3,1462.7
MSP_RC_OUT: P1.4 U1.18 | length 1702.6
  Top Layer w10: v5(336.86,890.55) 351.89,905.57 U1.18@413.02,905.57
  Signal Layer 2 w10: v5(336.86,890.55) 386.59,940.27 458.32,940.27 465.82,947.76 484.45,947.76 491.03,941.19 491.33,940.9 491.45,940.81 491.57,940.73 491.72,940.65 491.92,940.57 492.18,940.49 492.51,940.4 492.94,940.33 493.47,940.28 493.92,940.27 494.24,940.26 1320.93,940.26 1323.86,937.33 1499.18,762.01 1855.61,762.01 P1.4@1856.3,762.7
MSP_SCL: P1.10 U1.66 | length 844.4
  Top Layer w10: U1.66@1021.29,1063.06 1075.35,1063.06 1083.57,1071.27 1105.17,1071.27 v2(1108.15,1074.25)
  Bottom Layer w10: v2(1108.15,1074.25) 1111.13,1071.27 1847.73,1071.27 P1.10@1856.3,1062.7
MSP_SDA: P1.12 U1.65 | length 906.2
  Top Layer w10: U1.65@1021.29,1043.37 1120.23,1043.37 1157.96,1081.1 1157.96,1100.14 v2(1160.95,1103.12)
  Bottom Layer w10: v2(1160.95,1103.12) 1468.16,1103.12 1480.95,1090.34 1783.94,1090.34 P1.12@1856.3,1162.7
MSP_VREF: P1.8 U1.4 | length 1869.9
  Top Layer w10: U1.4@413.02,1181.17 436.88,1181.17 440.66,1177.39 442.25,1177.39 451.57,1168.07 451.57,1166.48 504.96,1113.08 v5(504.96,970.37)
  Bottom Layer w10: v5(504.96,970.37) 504.96,861.59 627.79,738.76 972.86,738.76 971.69,739.93 1194.46,962.7 P1.8@1856.3,962.7
NetC15_1: C15.1 R9.1 U1.9 | length 314.6
  Top Layer w10: C15.1@275.05,1300.54 254.99,1280.49 254.99,1245.03 261.8,1238.22 271.54,1238.22 272.72,1237.04 327.94,1181.82 327.94,1138.31 383.17,1083.09 412.68,1083.09 U1.9@413.02,1082.74
NetC26_2: C26.2 J10.1 R64.2 | length 185.9
  Top Layer w15: R64.2@916.87,1801.66 942.95,1801.66 ; J10.1@951,1672.02 942.95,1680.07 942.95,1801.66 ; C26.2@969.55,1801.15 969.03,1801.66 942.95,1801.66
NetC27_2: C27.2 J10.3 R65.2 | length 188.8
  Top Layer w15: R65.2@810.39,1800.81 810.73,1801.15 863.33,1801.15 C27.2@863.56,1801.37 ; 836.51,1801.37 836.51,1751.38 851,1736.89 J10.3@851,1672.02
NetC38_1: C38.1 C40.1 R68.2 U3.1 | length 559.7
  Top Layer w10: C40.1@865.88,2614.85 865.88,2610.91 889.38,2587.42 894.3,2587.42 895.16,2586.55 913.84,2586.55 C38.1@914.83,2585.56 ; C38.1@914.83,2584.16 v1(939.61,2559.38) 941.46,2561.23 954.98,2561.23 959.45,2565.71 969.45,2565.71 1013.51,2521.65 U3.1@1021.31,2521.65 ; R68.2@1161.04,2305.91 v1(1161.04,2360.42)
  Bottom Layer w15: v1(939.61,2559.38) 940.88,2559.38 957.53,2542.73 979.31,2542.73 1161.04,2360.99 v1(1161.04,2360.42)
NetC39_1: C39.1 U3.3 | length 138.5
  Top Layer w10: C39.1@998.09,2429.22 998.09,2463.85 1031.2,2496.97 1057.19,2496.97 1072.49,2512.27 U3.3@1072.49,2521.65
NetC44_2: C44.2 U1.14 Y2.1 | length 182.4
  Top Layer w10: C44.2@279.52,938.79 281.68,938.79 288.5,945.6 288.5,987.5 Y2.1@291,990 ; Y2.1@293.25,992.28 300.06,985.47 314.29,985.47 315.76,984 U1.14@415,984
NetC45_1: C45.1 U1.13 Y2.2 | length 221
  Top Layer w10: C45.1@254.9,1084.82 255.24,1085.17 271.63,1085.17 272,1084.8 276.6,1084.8 276.6,1034.53 283.13,1028 Y2.2@293,1028 ; Y2.2@293.25,1027.72 300.06,1020.91 355.09,1020.91 372,1004 U1.13@413.02,1004
NetC49_2: C49.2 U1.27 | length 79.4
  Top Layer w10: U1.27@500.62,699.87 500.97,699.52 500.97,628.4 C49.2@506.47,622.9
NetC50_1: C50.1 R37.2 U1.11 | length 255.5
  Top Layer w10: R37.2@261.69,1188.78 255.83,1182.92 255.83,1174.64 257.45,1173.02 257.45,1154.1 268.02,1143.53 269,1143.53 C50.1@272.13,1140.4 ; C50.1@264.89,1140.4 273.11,1140.4 286.82,1126.7 286.82,1111.23 354.68,1043.37 U1.11@413.02,1043.37
NetD1_2: D1.2 R58.2 | length 69.7
  Top Layer w10: R58.2@217.05,2256.48 217.05,2268.15 241.42,2292.52 D1.2@241.42,2316.06
NetD2_2: D2.2 R59.2 | length 59.4
  Top Layer w10: R59.2@139.47,2256.43 D2.2@139.47,2315.85
NetD4_1: D4.1 R11.2 | length 68.8
  Top Layer w10: D4.1@3796.14,748.22 3796.14,681.99 R11.2@3797.99,680.14
NetD5_1: D5.1 R42.2 | length 65.4
  Top Layer w25: R42.2@388.5,325.71 388.65,325.85 388.65,390.84 D5.1@388.79,390.98
NetD6_1: D6.1 R43.2 | length 65.2
  Top Layer w25: R43.2@587.12,325.23 D6.1@587.12,390.47
NetD8_1: D8.1 R45.2 | length 66.2
  Top Layer w25: R45.2@785.74,323.23 D8.1@785.74,389.47
NetD10_1: D10.1 R47.2 | length 66.2
  Top Layer w25: R47.2@984.35,322.23 D10.1@984.4,388.5
NetD11_1: D11.1 R48.2 | length 66.8
  Top Layer w25: D11.1@1181.8,388.5 1182.38,387.92 1182.38,322.82 R48.2@1182.97,322.23
NetF1_1: F1.1 J8.2 VSUP.1
  other v3: 3205.9,250.78 3280.8,250.78 3358.88,250.78 3425.28,250.78 3630.79,256.02 3358.88,357.02 3425.28,357.02 3493.8,357.02 3567.11,357.02 3630.79,362.26 3206.33,436.46 3281.22,436.46 3359.31,436.46 3425.71,436.46 3631.21,441.71 3205.9,516.1 3280.8,516.1 3358.88,516.1 3425.28,516.1 3630.79,521.35
NetJ6_2: J6.2 S1.1 S1.2 | length 498.4
  Top Layer w15: J6.2@1274,1653.91 1274,1786.46 S1.2@1210.2,1850.26 S1.1@1485.8,1850.26
NetJ9_2: J9.2 R63.1 | length 171.2
  Top Layer w10: R63.1@801.84,2843.55 802.83,2843.55 813.57,2854.3 813.57,2971.32 825.43,2983.17 J9.2@825.43,3004.4
NetJ9_4: J9.4 R62.1 | length 170
  Top Layer w10: J9.4@725.43,3004.4 725.43,2983.25 741.97,2966.7 741.97,2849.91 R62.1@748.08,2843.8
NetJ10_5: J10.5 R66.2 | length 132
  Top Layer w15: J10.5@751,1672.02 757.89,1678.91 757.89,1797.24 R66.2@757.89,1801.18
NetJ10_7: J10.7 R67.2 | length 150.6
  Top Layer w15: J10.7@651,1672.02 651,1750.92 698.9,1798.82 R67.2@698.9,1802.76
NetJ11_1: J11.1 L1.1 | length 83.3
  Top Layer w10: J11.1@1215,3020.01 1215,2983.22 L1.1@1247.92,2950.3
NetJ11_5: J11.5 L2.1 | length 111.9
  Top Layer w10: L2.1@1046.9,2956.86 1083.62,2956.86 1112.64,2985.88 J11.5@1112.64,3020.01
NetR3_1: R3.1 U4.8 | length 228.5
  Top Layer w15: R3.1@3802.74,277.13 3841.12,277.13 3902.91,338.92 U4.8@3902.91,441.66
NetR4_2: R4.2 U4.1 | length 3567.8
  Top Layer w15: R4.2@1941.22,2645.82 1941.22,2704.82 v2(1942.22,2705.82) ; v2(4069.04,442.5) 4116.64,442.5 U4.1@4117.48,441.66
  Signal Layer 2 w30: v2(1942.22,2705.82) 1946.2,2709.79 2469.21,2709.79 4069.04,1109.96 v2(4069.04,442.5)
NetR5_2: R5.2 U5.2 | length 54.3
  Top Layer w10: R5.2@3116.46,1534.5 3120.35,1534.5 3120.35,1554.5 3122.61,1556.76 U5.2@3122.61,1583.93
NetTP1_1: TP1.1 U1.22 | length 439.8
  Top Layer w10: v5(349.91,814.73) 362.02,826.83 U1.22@413.02,826.83
  Bottom Layer w10: TP1.1@173.74,516.01 173.74,522 289.56,637.81 289.56,754.37 v5(349.91,814.73)
NetTP2_1: TP2.1 U1.23 | length 565.4
  Top Layer w10: U1.23@413.02,807.15 470.04,807.15 v5(474.12,803.07) v5@474.46,802.74
  Signal Layer 2 w10: TP2.1@174.41,429.43 181.84,429.43 474.12,721.71 v5(474.12,803.07)
NetTP3_1: TP3.1 U1.21 | length 382.3
  Top Layer w10: v5(360.23,858.68) 372.4,846.52 U1.21@413.02,846.52
  Bottom Layer w10: TP3.1@175.74,610.59 175.74,622 274.56,720.81 274.56,773.01 v5(360.23,858.68)
NetTP4_1: TP4.1 U1.16 | length 793.1
  Top Layer w10: v1(362,944) 362.6,944.6 412.68,944.6 U1.16@413.02,944.94
  Bottom Layer w10: TP4.1@176,327 198.41,327 403.72,532.3 403.72,902.28 v1(362,944)
NetTP5_1: TP5.1 U1.88 | length 1777
  Top Layer w10: v1(476.01,1217.55) 500.86,1192.7 693.7,1192.7 716.81,1215.81 716.81,1307.79 U1.88@717.16,1308.13
  Signal Layer 1 w15: v1(110.64,1218.13) 109.93,1218.13 82.5,1190.7 82.5,296.58 137.79,241.29 139.46,241.29 158.75,222 TP5.1@176,222
  Signal Layer 2 w15: v1(110.64,1218.13) 111.53,1217.23 475.7,1217.23 v1(476.01,1217.55)
NetTP6_1: TP6.1 U1.42 | length 881.8
  Top Layer w10: v2(578.52,549.21) 670.68,549.21 792.12,670.64 792.12,672.96 795.9,676.74 U1.42@795.9,699.87
  Bottom Layer w10: TP6.1@171.39,131.34 172.45,131.34 575.54,534.43 575.54,546.22 v2(578.52,549.21)
nFAULT: P1.1 R24.2 R48.1 TP28.1 U5.4 | length 2689.2
  Top Layer w10: v1(1183.63,215) 1508.6,215 1972.46,678.85 2171.27,678.85 TP28.1@2176.18,683.77 2397.69,683.77 2918.44,1204.52 R24.2@2918.44,1205.5 2952.14,1205.5 3161.98,1415.35 U5.4@3161.98,1583.93
  Top Layer w25: R48.1@1182.97,259.24 1182.97,215.65 v1(1183.63,215)
nSLEEP: P1.17 TP36.1 U5.11 | length 1286
  Top Layer w10: P1.17@1956.3,1462.7 1965.56,1471.96 2166.92,1471.96 TP36.1@2176.18,1481.23 2535.5,1481.23 2770.26,1715.98 3110.63,1715.98 3122.34,1704.27 3122.34,1694.44 U5.11@3122.61,1694.17
OUT1: C4.2 C5.2 J1.1 TP8.1 U5.6 | length 82.2
  Top Layer w10: U5.6@3187.57,1629.21 3253.51,1629.21 3260.67,1622.04
  Top Layer w30: J1.1@4207.58,1516.35 J1.1@4211.94,1520.72
OUT2: C5.1 C8.2 J1.2 TP10.1 U5.8 | length 61.6
  Top Layer w10: U5.8@3187.57,1668.58 3244.09,1668.58 3247.28,1671.77
  Top Layer w30: J1.2@4211.57,1771.09 J1.2@4211.94,1770.72
PUSH: J6.3 U1.36 | length 1169.8
  Top Layer w10: U1.36@677.79,699.87 677.79,885.85 880.76,1088.82 880.76,1090.55 881.5,1091.3 881.5,1142.04 927.12,1187.66 v5(944.51,1187.66)
  Signal Layer 1 w14: v2(1073.98,1430.02) 1099,1455.04 1099,1578.91 J6.3@1174,1653.91
  Bottom Layer w10: v5(944.51,1187.66) 1051.43,1294.59 1051.43,1407.47 v2(1073.98,1430.02)
RC_OUT: P1.3 R1.2 TP29.1 U5.3 | length 1621.7
  Top Layer w10: P1.3@1956.3,762.7 1963.18,769.58 2265.3,769.58 TP29.1@2272.18,776.47 2413.95,776.47 2842,1204.52 R1.2@2842,1205.5 ; 3142.3,1462.3 U5.3@3142.3,1583.93
  Top Layer w12: R1.2@2842,1205.5 2842,1206.49 2888.74,1253.22 2888.74,1292.74 2973.52,1377.52 3057.52,1377.52 3142.3,1462.3
RC_OUT_DAC: TP7.1 U1.3 | length 237.3
  Top Layer w10: TP7.1@355.7,1390.57 355.7,1217.52 372.38,1200.85 U1.3@413.02,1200.85
RST/SBWTDIO: C41.2 C59.2 J6.1 J10.4 R18.2 R19.1 U1.96 | length 2785.8
  Top Layer w10: U1.96@559.68,1308.13 560.02,1308.48 560.02,1337.99 571.58,1349.55 574.73,1349.55 582.44,1357.26 v1(607.79,1357.26) ; v1(614.19,1620.16) 751.92,1617.36 cw(c751,1572.02) 774.14,1611.03 839.91,1572.02 J10.4@851,1572.02 905.65,1626.66 1055.75,1626.66 v1(1142,1712.91) ; v2(1216.22,2124.8) 1476.32,2124.8 1806.69,2455.16 1806.69,2461.07 1866.85,2461.07 R19.1@1866.92,2461.14 ; v1(1323.97,1702.32) 1324.78,1702.32 1373.19,1653.91 J6.1@1374,1653.91 1385.24,1665.15 1488.8,1665.15 C41.2@1511.79,1688.14
  Top Layer w15: R18.2@725.79,1414.72 733,1421.93 733,1438.06 v1(733.9,1438.96)
  Bottom Layer w10: v1(607.79,1357.26) 605.94,1359.12 605.94,1371.81 605.65,1372.11 605.65,1608.99 614.19,1617.54 v1(614.19,1620.16)
  Bottom Layer w15: v1(607.79,1357.26) 625.14,1357.26 631.85,1363.98 631.85,1368.41 701.56,1438.11 733.05,1438.11 v1(733.9,1438.96) ; v2(1216.22,2124.8) 1215.34,2123.91 1215.34,2105.77 1142,2032.43 v1(1142,1712.91) 1312.11,1712.91 1322.71,1702.32 v1(1323.97,1702.32)
SCL: P1.9 R7.2 TP32.1 U5.15 | length 1412.4
  Top Layer w10: 2967.24,1629.21 U5.15@3077.34,1629.21
  Top Layer w12: P1.9@1956.3,1062.7 1970.63,1062.7 1990.43,1082.5 TP32.1@2176.18,1082.5 2517.29,1082.5 2636.19,1201.4 2636.19,1211.5 2692,1267.32 2692,1353.97 2967.24,1629.21
SDA: P1.11 R6.2 TP33.1 U5.14 | length 1358.3
  Top Layer w10: 2979.83,1648.89 U5.14@3077.34,1648.89
  Top Layer w12: P1.11@1956.3,1162.7 1964.5,1170.9 2263.98,1170.9 TP33.1@2272.18,1179.1 2536.66,1179.1 2567,1209.44 2567,1217.32 2618.2,1268.52 2618.2,1321.86 2945.24,1648.89 2979.83,1648.89
STALL: D10.2 U1.20 | length 732.3
  Top Layer w10: U1.20@413.02,866.2 456.28,866.2 v5(472.79,849.69) ; v5(920.58,455.87) 969.18,455.87 D10.2@973.56,451.5
  Bottom Layer w10: v5(472.79,849.69) 866.61,455.87 v5(920.58,455.87)
T_RST_RST: R65.1 U2.43 | length 355.5
  Top Layer w10: U2.43@761.03,2144.7 854.66,2051.08 854.66,1915.25 844.41,1905.01 844.41,1886.19 846.47,1884.13 R65.1@810.39,1848.06
T_TEST_TCKC: R64.1 U2.44 | length 375.3
  Top Layer w10: U2.44@770.13,2163.44 916.87,2016.7 R64.1@916.87,1848.91
TST/SBWTCK: J10.2 U1.91 | length 475.4
  Top Layer w10: v1(657.07,1357.96) 658.1,1356.93 U1.91@658.1,1308.13 ; v1(719.58,1378.15) 717.92,1379.81 720.02,1381.91 818,1381.91 v1(937.08,1501) 937.08,1558.1 J10.2@951,1572.02
  Bottom Layer w10: v1(657.07,1357.96) 680.58,1381.47 708.99,1381.47 715.94,1374.52 v1(719.58,1378.15)
USB_D_N: J11.2 R72.1 U6.3 | length 622.1
  Top Layer w10: v1(1125.79,2808) 1159.94,2773.85 R72.1@1159.94,2687.19 ; U6.3@1175.4,2895.77 1175.4,2883.14 1175.72,2882.82 ; J11.2@1189.41,3020.01 1189.95,3019.46 1189.95,2953.43 1194.18,2949.2 1194.18,2901.28 1175.72,2882.82 ; v1(1214,2785) 1175.72,2823.28 1175.72,2882.82
  Bottom Layer w10: v1(1104.46,2915) 1104.46,2829.33 v1(1125.79,2808) 1191,2808 v1(1214,2785)
USB_D_P: J11.3 R75.1 U6.2 U6.5 U6.6 | length 390.1
  Top Layer w10: J11.3@1163.82,3020.01 1163.82,2975.6 1158.39,2970.17 1157.83,2970.17 1136.03,2948.38 U6.6@1136.03,2919.39 U6.5@1155.72,2919.39 U6.2@1155.72,2895.77 1155.72,2811.16 1208.37,2758.5 R75.1@1208.37,2683.26
VM: C1.2 C6.1 C55.1 C56.2 C57.2 C58.2 D4.2 F1.2 R3.2 R12.2 U5.5 VM.1 | length 385.4
  Top Layer w10: R12.2@3662.94,817.83 3662.94,780.18 3694.9,748.22 D4.2@3733.15,748.22
  Top Layer w15: 3710.99,523.7 3710.99,449.13 3707.87,446 3707.87,375.74 3744.46,339.14 3744.46,280.28 R3.2@3747.62,277.13
  other v3: 3217.43,609.67 3296.72,609.67 3376.01,609.67 3455.31,609.67 3534.6,609.67 3613.89,609.67 3693.18,609.67 3494.21,668.9 3577.27,668.9 3217.56,675.56 3296.86,675.56 3376.15,675.56 3693.18,705.85 3455.31,728.52 3534.6,728.52 3613.89,728.52 3613.89,782.17 3228.18,822.81 3307.48,822.81 3386.77,822.81 3217.56,883.87 3476.21,922.23 3272.2,999.66 3331.88,1049.6 3261.71,1099.2
VREF: P1.7 TP31.1 U5.16 | length 1456.1
  Top Layer w10: P1.7@1956.3,962.7 1963.84,970.24 2264.64,970.24 TP31.1@2272.18,977.79 2478.65,977.79 2722.08,1221.21 2722.08,1335.79 2995.81,1609.52 U5.16@3077.34,1609.52
VSEN_VM: C60.2 R12.1 R35.2 U1.97 | length 5275.6
  Top Layer w10: U1.97@539.99,1308.13 540.34,1307.79 540.34,1271.28 568.78,1242.85 v1(569.59,1242.85) ; v1@840,1353 840,1365.8 v1(1104.91,1630.71) ; v2(1155.24,2098.63) 1156.89,2100.28 1485.49,2100.28 v2(1774.91,2389.71) ; C60.2@2128,2442.11 2139.11,2431 R35.2@2188,2431 ; v2(2188,2388) 2188,2429 R35.2@2189,2430
  Top Layer w15: R12.1@3707.48,862.38 3739.97,894.87 3739.97,909.97 v2(3742,912)
  Signal Layer 2 w15: v2@1775,2390 1777,2388 v2(2188,2388) 2691,2388 3742,1337 v2(3742,912)
  Bottom Layer w10: v1(569.59,1242.85) 569.59,1092.5 584.81,1077.28 628.85,1077.28 688.23,1136.67 688.23,1202.23 v1(841,1355)
  Bottom Layer w15: v1@1103.04,1631 1104.91,1632.87 1104.91,2048.31 v2(1155.24,2098.63)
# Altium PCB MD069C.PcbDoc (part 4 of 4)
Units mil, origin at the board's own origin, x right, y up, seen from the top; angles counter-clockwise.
Board outline 4569 x 3239 mil, 4 copper layers (Top Layer, Signal Layer 1, Signal Layer 2, Bottom Layer), stack 61.2 mil thick; 192 components, 101 nets, 567 pads, 224 vias.
Unrouted connection lines stored in the file: 7.

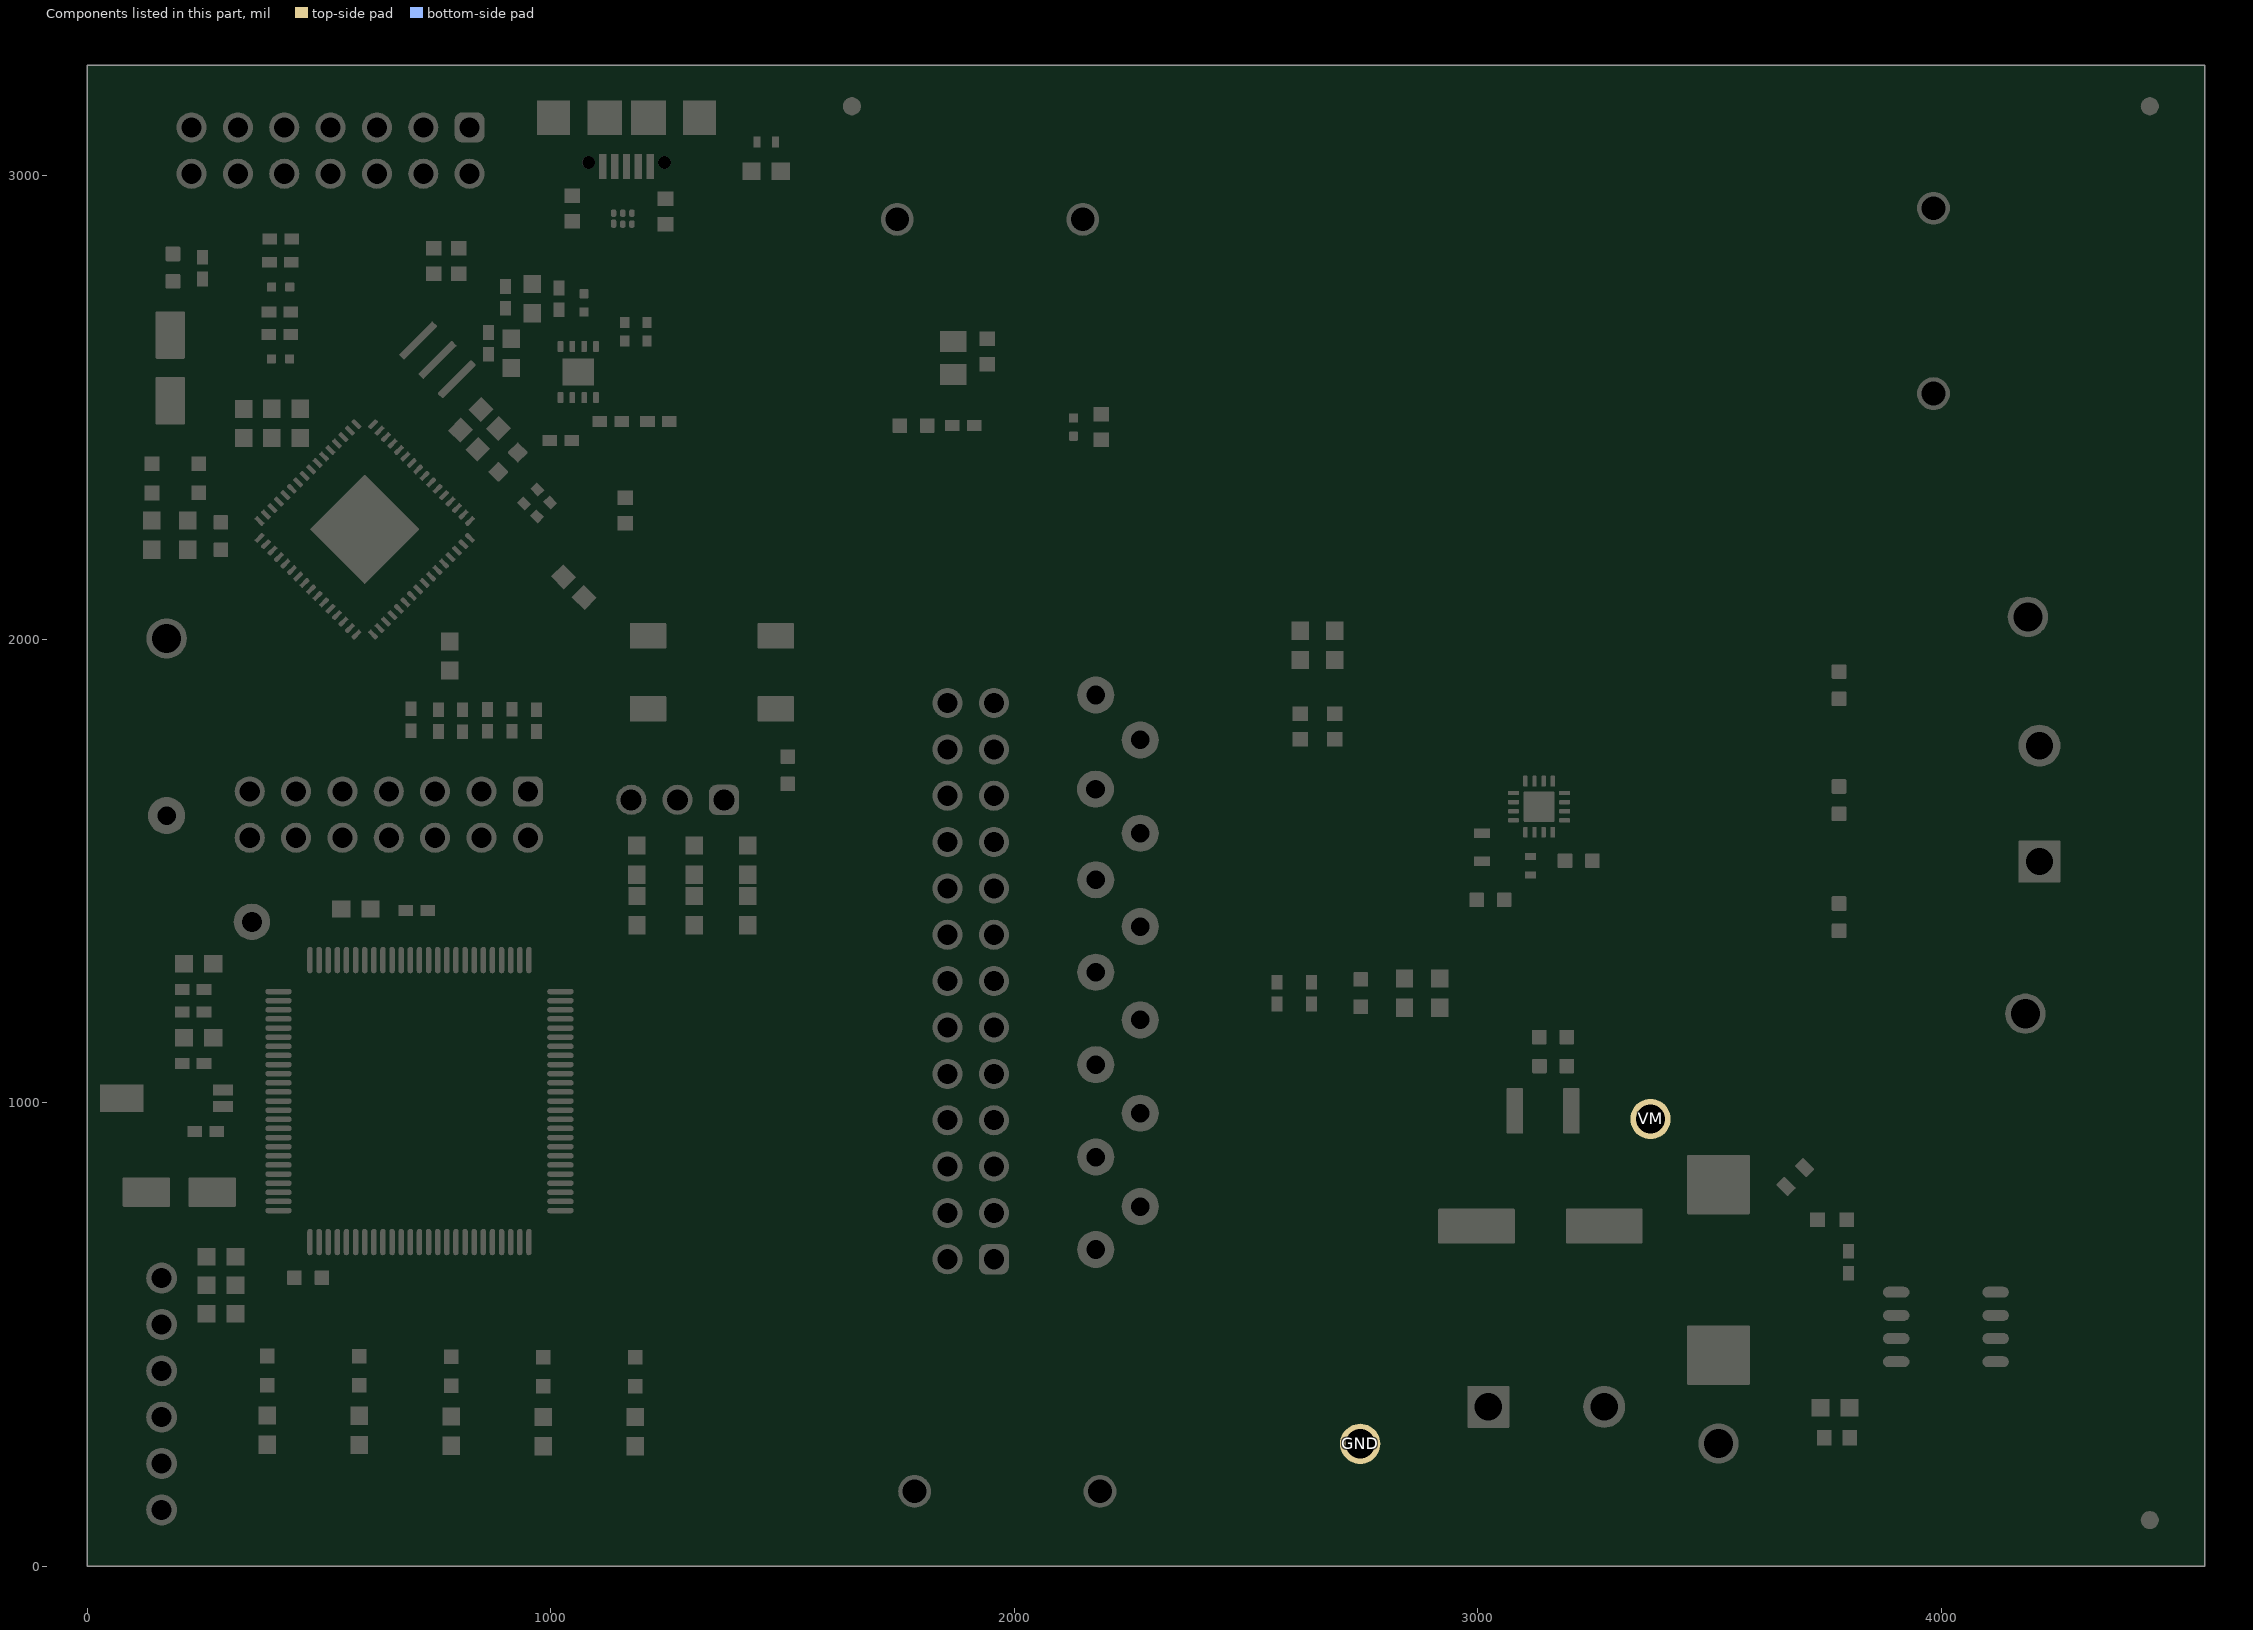
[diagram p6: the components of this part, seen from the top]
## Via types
v1: diameter 19.68, hole 13.78, Top Layer to Bottom Layer, tented both sides, 92 vias
v2: diameter 25.59, hole 13.78, Top Layer to Bottom Layer, tented both sides, 49 vias
v3: diameter 34, hole 16, Top Layer to Bottom Layer, tented both sides, 47 vias
v4: diameter 19.68, hole 7.87, Top Layer to Bottom Layer, 16 vias
v5: diameter 25/25/25/25 (per signal layer), hole 12, Top Layer to Bottom Layer, 11 vias
v6: diameter 19.68, hole 7.87, Top Layer to Bottom Layer, tented both sides, 5 vias
v7: diameter 23.62, hole 13.78, Top Layer to Bottom Layer, tented both sides, 4 vias

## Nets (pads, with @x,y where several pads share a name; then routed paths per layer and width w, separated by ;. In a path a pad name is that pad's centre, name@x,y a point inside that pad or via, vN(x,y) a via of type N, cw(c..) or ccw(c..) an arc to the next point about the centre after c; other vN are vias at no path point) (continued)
pads on no net: FID1.1 FID2.1 FID3.1 H2.0 H3.0 H4.0 H5.0 J9.6 J9.10 J9.12 J9.13 J9.14 J10.11 J10.12 J11.4 J11.MH1 J11.MH2 LBL1.0 P1.20 P1.22 SH-J1.0 SH-J2.0 SH-J3.0 SH-J4.0 SH-J5.0 SH-J6.0 SH-J7.0 SH-J8.0 SH-J9.0 SH-J10.0 SH-J11.0 SH-J12.0 SH-J19.0 SH-J29.0 SH-J31.0 SH-J32.0 SH-J33.0 SH-J34.0 SH-J36.0 U1.1 U1.2 U1.5 U1.6 U1.7 U1.8 U1.19 U1.24 U1.28 U1.30 U1.34 U1.35 U1.37 U1.38 U1.39 U1.40 U1.41 U1.45 U1.46 U1.47 U1.48 U1.50 U1.52 U1.54 U1.55 U1.56 U1.57 U1.58 U1.59 U1.62 U1.67 U1.68 U1.69 U1.70 U1.71 U1.72 U1.73 U1.74 U1.75 U1.77 U1.78 U1.79 U1.80 U1.81 U1.82 U1.84 U1.85 U1.86 U1.92 U1.93 U1.94 U1.95 U1.99 U1.100 U2.3 U2.4 U2.5 U2.6 U2.7 U2.8 U2.10 U2.12 U2.13 U2.18 U2.19 U2.22 U2.23 U2.24 U2.25 U2.26 U2.27 U2.28 U2.29 U2.30 U2.31 U2.32 U2.33 U2.34 U2.35 U2.36 U2.41 U2.42 U2.45 U2.46 U2.47 U2.48 U3.2 U3.6 U3.7

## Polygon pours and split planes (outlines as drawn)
NetF1_1 on Signal Layer 2 "SIGNAL_LAYER_2_NETF1_1_P136" (solid, remove dead copper, pour order 136): 3178.98,547.2 3169.14,537.36 3169.14,221.09 3696.72,221.09 3696.72,547.2
GND on Signal Layer 2 "SIGNAL_LAYER_2_GND_P275" (solid, pour order 275): 0,0 4569,0 4569,3239 0,3239
EZFET_VBUS on Signal Layer 2 "SIGNAL_LAYER_2_EZFET_VBUS_P199" (solid, remove dead copper, pour order 199): 873.67,3236.65 1498.38,3236.65 1498.38,2692.6 875.05,2692.6
NetF1_1 on Bottom Layer "BOTTOM_LAYER_NETF1_1_P273" (solid, remove dead copper, pour order 273): 3178.98,547.2 3169.14,537.36 3169.14,221.09 3666.78,221.09 3666.78,547.2
VM on Bottom Layer "Top Layer-VM" (solid, remove dead copper, pour order 289): 3176.21,550.76 3590.5,550.76 3727.75,500.04 3727.75,770.58 3283.23,1160.21 3176.24,1160.21 3176.21,1160.21
GND on Bottom Layer "BOTTOM_LAYER_GND_P290" (solid, remove dead copper, pour order 290): 4569,3239 14.6,3239 14.6,16.09 4569,16.09
VM on Top Layer "Top Layer-VM" (solid, remove dead copper, pour order 276): 3174.2,551.21 3588.49,551.21 3725.74,500.49 3725.74,771.03 3281.22,1160.66 3281.21,1160.66 3206.52,1235.35 3206.52,1614.25 3174.23,1614.25 3174.23,1160.66 3174.2,1160.66
OUT2 on Top Layer "Top Layer-OUT2" (solid, remove dead copper, pour order 283): 3234.99,1663.78 4289.2,1663.78 4289.2,1895.76 4289.19,2096.66 4033.49,2096.66 4033.49,1895.76 3454.57,1895.76 3234.99,1676.18
OUT1 on Top Layer "Top Layer-OUT1" (solid, remove dead copper, pour order 281): 4033.71,1125.09 4289.47,1125.09 4289.47,1576.66 4289.07,1576.66 4289.07,1635.4 3234.86,1635.4 3234.86,1623.01 3454.44,1403.43 4033.71,1403.43
NetF1_1 on Top Layer "TOP_LAYER_NETF1_1_P201" (solid, remove dead copper, pour order 201): 3178.98,547.2 3169.14,537.36 3169.14,221.09 3666.78,221.09 3666.78,547.2
GND on Top Layer "TOP_LAYER_GND_P284" (solid, remove dead copper, pour order 284): -2.31,0.73 4566.69,0.73 4566.69,3256.9 -2.31,3256.9
GND on Signal Layer 1 "SIGNAL_LAYER_1_GND_P184" (solid, pour order 184): 7.78,3237 4569,3237 4569,0 0,0

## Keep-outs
Keep-Out Layer:
  text ".Layer_Name" at 569,-2296.49 h25

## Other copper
Top Layer:
  region net EZFET_USB_Shield: 952,3211.2 952,3207.75 952,2988 1054.33,2988 1054.33,3047.1 1083.51,3070 1115.89,3070 1247.92,3070 1279.78,3038.14 1279.78,2993.31 1288.51,2993.31 1288.51,2994.8 1385.6,2994.8 1384,3210.75 1376.61,3210.75
  text ".Layer_Name" at 569,-2296.49 h25
Bottom Layer:
  region net EZFET_USB_Shield: 1383,2990.4 1384,2989.4 1281,2989.4 1281,3062.38 1279.38,3064 1054.47,3064 1054.47,2991.47 1052,2989 1051.6,2989.4 944.18,2989.4 944.18,3064 943,3064 943,3211.88 943.31,3211 944.18,3211.88 1383,3211.88
  text ".Layer_Name" at 569,-2296.49 h25

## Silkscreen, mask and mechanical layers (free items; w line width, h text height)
Top Overlay:
  circle w15: c3085.98,1554.04 r9.06
  circle w16: c363.12,1271.65 r8
  lines w6: 747.3,2445.12 846.73,2345.69 951.5,2450.46 ; 747.3,2452.46 846.73,2551.89 ; 774.9,3053.95 774.9,3145.38 ; 775.57,3053.95 871.06,3053.78 ; 852.07,2551.89 951.5,2452.46 ; 902.63,1622.79 902.63,1714.21 ; 903.3,1622.79 998.79,1622.61 ; 932.77,2431.73 1000.46,2364.04 1244.04,2364.04 ; 1217.34,2335.34 1290.75,2261.94 ; 1219.35,2335.34 1280.74,2396.74 ; 1281.41,2396.74 1354.15,2324 ; 1290.75,2259.94 1354.15,2323.33 ; 2591.82,1784.05 2591.82,1760.87 2641.52,1760.87 2641.52,1784.34 ; 2592.48,1839.66 2592.48,1863.13 2642.18,1863.13 2642.18,1839.95 ; 2666.82,1784.05 2666.82,1760.87 2716.52,1760.87 2716.52,1784.34 ; 2667.48,1839.66 2667.48,1863.13 2717.18,1863.13 2717.18,1839.95 ; 178.97,2959.12 871.06,2959.12 871.06,3148.43 178.97,3148.43 178.97,2959.12 ; 306.7,1527.96 998.79,1527.96 998.79,1717.27 306.7,1717.27 306.7,1527.96
  lines w10: 747.3,2445.12 747.3,2452.46 ; 846.73,2551.89 852.07,2551.89 ; 890.45,3068.4 890.45,3141.92 ; 951.5,2450.46 951.5,2452.46 ; 1014.26,1636.12 1014.26,1709.64 ; 1217.34,2335.34 1219.35,2335.34 ; 1280.74,2396.74 1281.41,2396.74 ; 1290.75,2259.94 1290.75,2261.94 ; 1354.15,2323.33 1354.15,2324 ; 2011.81,661.28 2122.05,661.28 ; 2011.81,764.8 2220.47,764.8 ; 2011.81,863.64 2122.05,863.64 ; 2011.81,964.24 2220.47,964.24 ; 2011.81,1063.67 2122.05,1063.67 ; 2011.81,1163.1 2220.47,1163.1 ; 2011.81,1263.11 2122.05,1263.11 ; 2011.81,1361.95 2220.47,1361.95 ; 2011.81,1463.13 2122.05,1463.13 ; 2011.81,1559.64 2220.47,1559.64 ; 2011.81,1661.99 2122.05,1661.99 ; 2011.81,1765.51 2220.47,1765.51 ; 2011.81,1863.19 2122.05,1863.19 ; 747.3,2452.46 747.3,2452.46 ; 932.77,2431.73 932.77,2431.73 ; 2936.68,1382.99 2937.02,1382.66 3286.35,1382.66 3288.35,1384.66 3288.35,1804.25 3286.02,1806.58 2936.68,1806.58 2936.68,1382.99
  text "For EZFET-LITE Flashing Only" at 190,3170 h25
  text "GND" at 3930.02,3001.94 h60
  text "GND" at 1878.66,2980.62 h60
  text "1" at 549,2484.8 h25
  text "'.PRJ_Number'.PCB_Rev" at 3144.77,2412.85 h60
  text "RESET" at 1246,2080 h45
  text "3.3 V" at 2597.46,2059.89 h55
  text "OUT2" at 4394.98,1953.69 h60 r90
  text "DRV8214_34" at 2936.06,1901.34 h40
  text "A1" at 2590.36,1876.99 h35
  text "A0" at 2662.62,1876.99 h35
  text "3V3" at 2244,1870 h30
  text "GND" at 91.73,1852.74 h60
  text "DRV8215_35" at 2936.06,1827.34 h40
  text "GND" at 2344,1770.19 h30
  text "GND" at 371.51,1734.84 h35 r90
  text "NC" at 467.8,1734.84 h35 r90
  text "3V3" at 572.5,1734.84 h35 r90
  text "RX" at 624.94,1728.22 h35
  text "TX" at 718.86,1728.22 h35
  text "PUSH" at 1142,1712.91 h35
  text "RST" at 1345.31,1712.91 h35
  text "GND" at 2602,1712.65 h55
  text "3V3" at 90.11,1702.29 h60
  text "A1" at 2284.71,1668.61 h30
  text "A0" at 2378.88,1563.92 h30
  text "nSLEEP" at 2288.22,1469.17 h30
  text "IN2" at 2381.8,1370.91 h30
  text "IN1" at 2329.16,1262.13 h30
  text "ID1" at 1199,1255 h31.5 r90
  text "ID2" at 1321,1255 h31.5 r90
  text "ID3" at 1438,1255 h31.5 r90
  text "SDA" at 2361,1173 h30
  text "OUT1" at 4389.64,1090.84 h60 r90
  text "SCL" at 2290.56,1065.61 h30
  text "VREF" at 2367.76,967.35 h30
  text "IPROPI" at 2298.75,869.09 h30
  text "RC_OUT/RSVD" at 2377.71,769.99 h30
  text "nFAULT" at 2279.45,666.73 h30
  text "3V3" at 337.79,247.48 h40 r90
  text "GND" at 1910.63,225.93 h60
  text "MCU_STATUS" at 541.13,189.46 h40 r90
  text "GUI_STATUS" at 744.48,189.46 h40 r90
  text "STALL" at 941.15,189.46 h40 r90
  text "nFAULT" at 1137.83,189.46 h40 r90
  text ".Layer_Name" at 569,-2296.49 h25
Bottom Overlay:
  text ".Layer_Name" at 569,-2296.49 h25
Top Paste:
  text ".Layer_Name" at 569,-2296.49 h25
Bottom Paste:
  text ".Layer_Name" at 569,-2296.49 h25
Top Solder:
  text ".Layer_Name" at 569,-2296.49 h25
  text ".Layer_Name" at 569,-2296.49 h25
Bottom Solder:
  text ".Layer_Name" at 569,-2296.49 h25
Drill Guide:
  text ".Layer_Name" at 569,-2296.49 h25
M1 Board Outline:
  circle w10: c4736.09,-1182.09 r70.87
  circle w10: c247.91,-1693.91 r70.87
  lines w10: -9,7 -4,3209 ; -9,3243 4572,3240 ; -6,-4 4289,0 ; 4569,3242 4570,3
  text ".Layer_Name" at 569,-2296.49 h25
M2 Board Dimensions:
  rectangle: -8,-1713 117,-1588
  rectangle: 117,-1838 492,-1713
  lines w7: -8,-1713 992,-1713 ; 117,-1838 117,-1588 ; 242,-1838 242,-1588 ; 492,-1838 492,-1588 ; 742,-1838 742,-1588 ; -8,-1838 992,-1838 992,-1588 -8,-1588 -8,-1838
  text ".Layer_Name" at 569,-2296.49 h25
M3 3D STEP Top:
  text ".Layer_Name" at 569,-2296.49 h25
M4 3D STEP Bottom:
  text ".Layer_Name" at 569,-2296.49 h25
M5 Assembly Top:
  lines w10: -300,-2368.17 6300,-2368.17 ; -300,-2164.83 6302,-2164.83 ; -300,-1961.5 -300,-2571.5 3705,-2571.5 6302,-2571.5 6302,-1961.5 -299.5,-1961.5 -299.5,-2571.5 1276,-2571.5 ; 2165,-2571.5 2165,-1961.5 ; 3432,-2164.83 3432,-1961.5 ; 4272,-2164.83 4272,-1961.5 ; 4894,-2578 4894,-2375.17
  text "COMPONENTS MARKED 'DNP' SHOULD NOT BE POPULATED." at 1145.5,-1756.5 h25
  text "ASSEMBLY VARIANT:" at 1145,-1872 h25
  text ".VariantName" at 2181,-1872 h25
  text "PCB VIEWED FROM TOP SIDE" at -236.5,-2093.67 h25
  text "BOARD #:" at 2240,-2093.67 h25
  text ".PRJ_Number" at 2785.5,-2093.67 h25
  text "REV:" at 3630,-2093.67 h25
  text ".PCB_Rev" at 3921.5,-2093.67 h25
  text "SVN REV:" at 4468,-2093.67 h25
  text ".VersionControl_RevNumber" at 4974,-2093.67 h25
  text "TID #:" at 2240,-2297 h25
  text ".TID" at 2785.5,-2297 h25
  text "PLOT NAME =" at -236.5,-2502.34 h25
  text ".plot_File_Name" at 569,-2502.34 h25
  text "GENERATED    :" at 2242,-2502.34 h25
  text ".Print_Date" at 3111.5,-2502.34 h25
  text ".Print_Time" at 3840.5,-2502.34 h25
  text "TEXAS INSTRUMENTS" at 5105,-2502.34 h25
M6 Assembly Bottom:
  lines w10: -300.5,-2165.33 6301.5,-2165.33 ; -298.5,-2368.67 6301.5,-2368.67 ; 1107.5,-2578.5 1107.5,-2375.67 ; 1729.5,-2165.33 1729.5,-1962 ; 2569.5,-2165.33 2569.5,-1962 ; 3836.5,-2572 3836.5,-1962 ; 4725.5,-2572 6301,-2572 6301,-1962 -300.5,-1962 -300.5,-2572 2296.5,-2572 6301.5,-2572 6301.5,-1962
  text "COMPONENTS MARKED 'DNP' SHOULD NOT BE POPULATED." at 6094,-1756 h25
  text ".VariantName" at 5050,-1872 h25
  text "ASSEMBLY VARIANT:" at 6089,-1872 h25
  text ".VersionControl_RevNumber" at 1027.5,-2094.17 h25
  text "SVN REV:" at 1533.5,-2094.17 h25
  text ".PCB_Rev" at 2080,-2094.17 h25
  text "REV:" at 2371.5,-2094.17 h25
  text ".PRJ_Number" at 3216,-2094.17 h25
  text "BOARD #:" at 3761.5,-2094.17 h25
  text "PCB VIEWED FROM BOTTOM SIDE" at 6238,-2094.17 h25
  text ".TID" at 3216,-2297.5 h25
  text "TID #:" at 3761.5,-2297.5 h25
  text "TEXAS INSTRUMENTS" at 896.5,-2502.84 h25
  text ".Print_Time" at 2161,-2502.84 h25
  text ".Print_Date" at 2890,-2502.84 h25
  text "GENERATED    :" at 3759.5,-2502.84 h25
  text ".plot_File_Name" at 5432.5,-2502.84 h25
  text "PLOT NAME =" at 6238,-2502.84 h25
M9 Title Sheet:
  drawing of 57 lines, arcs and shapes, not listed
  text "1" at 731.84,6598.5 h25
  text "2" at 3227.5,6598.5 h25
  text "3" at 5716.84,6598.5 h25
  text "4" at 8223.51,6598.5 h25
  text "5" at 10722.5,6598.5 h25
  text "6" at 13227.5,6598.5 h25
  text "A" at -424.5,5455.5 h25
  text "A" at 14375.5,5455.5 h25
  text "B" at -424.5,3075.5 h25
  text "B" at 14375.5,3075.5 h25
  text "C" at -424.5,700.5 h25
  text "C" at 14375.5,700.5 h25
  text "PROJECT TITLE:" at 11335.5,-1160.5 h25
  text ".PRJ_Title" at 11385.5,-1293.83 h25
  text "DESIGNED FOR:" at 11335.5,-1461.5 h25
  text ".PRJ_Customer" at 11385.5,-1601.5 h25
  text "D" at -424.5,-1669.5 h25
  text "D" at 14375.5,-1669.5 h25
  text "FILE NAME:" at 11335.5,-1761.5 h25
  text ".PCB_File_Name_No_Path" at 11385.5,-1881.5 h25
  text "Texas Instruments (TI) and/or its licensors do not warrant the accuracy or completeness of this specification" at 6366,-2043.34 h25
  text "ENGINEER:" at 11335.5,-2051.5 h25
  text "LAYOUT BY:" at 12840.5,-2051.5 h25
  text "or any information contained therein. TI and/or its licensors do not warrant that this design will meet" at 6321.01,-2156 h25
  text ".PRJ_Engineer" at 11385.5,-2206.49 h25
  text ".PCB_Layout" at 12891,-2206.49 h25
  text "the specifications, will be suitable for your application or fit for any particular purpose, or will operate in" at 6321.01,-2268.67 h25
  text ".Layer_Name" at 569,-2296.49 h25
  text "ALTIUM DESIGNER VERSION:" at 12840.5,-2361.5 h25
  text "an implementation. TI and/or its licensors do not warrant that the design is production worthy. You should" at 6321.01,-2381.33 h25
  text "completely validate and test your design implementation to confirm the system functionality for your application." at 6366,-2494 h25
  text ".print_Scale" at 11385.5,-2494.83 h25
  text ".Application_BuildNumber" at 12891,-2494.83 h25
  text "1" at 731.84,-2701.5 h25
  text "2" at 3227.5,-2701.5 h25
  text "3" at 5716.84,-2701.5 h25
  text "4" at 8223.51,-2701.5 h25
  text "5" at 10722.5,-2701.5 h25
  text "6" at 13227.5,-2701.5 h25
M10 Fab Notes:
  drawing of 189 lines, arcs and shapes, not listed
  text "DESIGN INFORMATION" at 12374.02,4918.17 h25
  text "MIN. TRACK WIDTH:" at 11729.46,4786.05 h25
  text "8" at 12825.7,4786.05 h25
  text "MIL" at 12980.46,4786.05 h25
  text "MIN. CLEARANCE:" at 11729.46,4661.92 h25
  text "0.2" at 12765.7,4661.93 h25
  text "mm" at 12980.46,4661.92 h25
  text "MIN. VIA PAD SIZE:" at 11729.46,4537.8 h25
  text "24" at 12795.71,4537.8 h25
  text "MIL" at 12980.46,4537.8 h25
  text "0.05mm (2MIL)" at 12424.46,4407.9 h25
  text "MINIMUM ANNULAR RING" at 11400.23,4399.67 h25
  text "EXTERNAL" at 13132.46,4399.67 h25
  text "PER" at 11600.23,4289.55 h25
  text "IPC-D-275 CLASS 2 LEVEL C" at 11820.23,4289.54 h25
  text "MIL, HOLES" at 13308.46,4189.07 h25
  text "+/-" at 12916,4180.48 h25
  text "+/-" at 13770,4180.48 h25
  text "REGISTRATION TOLERANCES:" at 11400.23,4179.42 h25
  text "METAL" at 12600,4179.42 h25
  text "5" at 13176.2,4179.42 h25
  text "3" at 14009.2,4179.42 h25
  text "MIL" at 14125.46,4179.42 h25
  text "HOLE SIZE TOLERANCE (UNLESS OTHERWISE SPECIFIED):" at 11400.23,4081.1 h25
  text "+/-" at 13770,4078.23 h25
  text "3" at 14009.2,4077.17 h25
  text "MIL" at 14125.46,4077.17 h25
  text "MATERIAL:" at 11325.46,3939.52 h25
  text "FR-4 High Tg" at 12311.9,3811 h25
  text "X" at 12167.46,3803.01 h25
  text "FR-408" at 11746.46,3798.49 h25
  text "OTHER" at 13234.46,3798.49 h25
  text "62 MIL (1.6mm) +/-10%" at 12066.56,3655.46 h25
  text "X" at 11946.46,3653.01 h25
  text "THICKNESS:" at 11400.23,3647.24 h25
  text "OTHER" at 13351.46,3647.24 h25
  text "TOLERANCE:" at 11400.23,3508.92 h25
  text "X" at 12248.46,3508.92 h25
  text "ANSI IPC-6012 TYPE 3 CLASS 2" at 12426.48,3508.92 h25
  text "OTHER +/-" at 12426.46,3364.73 h25
  text "BOW & TWIST:" at 11400.23,3219.54 h25
  text "X" at 12248.46,3219.54 h25
  text "ANSI IPC-6012 TYPE 3 CLASS 2" at 12426.48,3219.54 h25
  text "OTHER +/-" at 12426.46,3072.85 h25
  text "DRILLING:" at 11325.46,2942.23 h25
  text "NC_DRILL FILES" at 13086.46,2837.04 h25
  text "REFERENCE:" at 11400.23,2833.1 h25
  text "X" at 12057.46,2833.01 h25
  text "AS SHOWN" at 12235.46,2833.1 h25
  text "X" at 12958.46,2833.1 h25
  text "OTHER" at 13384.46,2690.85 h25
  text "PTH COPPER THICKNESS:" at 11399.91,2687.32 h25
  text "X" at 12539.14,2687.32 h25
  text "20-30 um" at 12667.14,2687.32 h25
  text "BOARD FINISH:" at 11325.46,2539.73 h25
  text "SILKSCREEN:" at 11480.68,2429.6 h25
  text "X" at 12438.46,2429.6 h25
  text "TOP" at 12555.46,2429.6 h25
  text "X" at 12948.46,2429.6 h25
  text "BOTTOM" at 13066.46,2429.6 h25
  text "SILKSCREEN COLOR:" at 11480.68,2274.41 h25
  text "X" at 12437.46,2274.41 h25
  text "WHITE" at 12555.46,2274.41 h25
  text "OTHER" at 13066.46,2274.41 h25
  text "X" at 12568.46,2130.96 h25
  text "GREEN" at 12686.46,2130.96 h25
  text "OTHER" at 13304.46,2130.96 h25
  text "SOLDER RESIST COLOR:" at 11480.68,2124.1 h25
  text "X" at 12568.46,1976.71 h25
  text "MATTE" at 12686.46,1976.71 h25
  text "SEMI-GLOSS" at 13304,1976.07 h25
  text "IMMERSION GOLD (ENIG)" at 12386.46,1803.94 h25
  text "ENEPIG" at 13724,1796.72 h25
  text "SURFACE FINISH:" at 11325.46,1795.72 h25
  text "X" at 12208.46,1795.72 h25
  text "IMM. TIN/SILVER OR EQUIV" at 11655,1658.4 h25
  text "OTHER" at 13086.46,1654.47 h25
  text "ARRAY/PANEL:" at 11325.46,1499.09 h25
  text "CUT AND TRIM PER M1 BOARD OUTLINE" at 12386.46,1490.87 h25
  text "N.C. ROUTE" at 12386.46,1354.9 h25
  text "X" at 13074.46,1354.9 h25
  text "V. SCORE" at 13252.46,1354.9 h25
  text "CERTIFICATION:" at 11325.46,1225.77 h25
  text "MATERIALS AND WORKMANSHIP FOR ALL PCBS" at 12050.46,1225.77 h25
  text "TO MEET OR EXCEED THE REQUIREMENTS OF:" at 12050.46,1131.71 h25
  text "X" at 11687.97,1003.08 h25
  text "ANSI IPC-A-600F CLASS ->" at 11815.96,1003.08 h25
  text "X" at 13463.97,1003.08 h25
  text "2" at 13573.96,1003.08 h25
  text "1" at 13258.96,1001.58 h25
  text "3" at 13927.96,1001.58 h25
  text "X" at 12499.97,855.39 h25
  text "RoHS" at 12627.96,855.39 h25
  text "OTHER" at 13272.36,855.39 h25
  text "PER ORDER" at 13669.42,855.39 h25
  text "ALL BOARDS MUST MEET OR EXCEED UL94-V0 REQUIREMENTS." at 11353,701.57 h25
  text "PCB MUST BEAR THE UL94V-0 UL REGISTERED MATERIAL ID NUMBER" at 11353,585.5 h25
  text "ADDITIONAL REQUIREMENTS:" at 11325.46,416.08 h25
  text "MICROSECTION:" at 11400.23,308.95 h25
  text "YES" at 12305.96,308.95 h25
  text "REQUIRED" at 13167.46,164.62 h25
  text "BARE BOARD ELEC. TEST:" at 11400.23,161.76 h25
  text "NONE" at 12705.96,161.76 h25
  text "X" at 13049.46,161.76 h25
  text "PER ORDER" at 13759.46,161.76 h25
  text "XX MIL VIAS REQUIRE NON-CONDUCTIVE FILL AND PLANARIZE" at 11568.38,-43.18 h25
  text "XX MIL VIAS REQUIRE CONDUCTIVE FILL AND PLANARIZE" at 11576.38,-147.16 h25
  text "OUTER XX MIL TRACES REQUIRE 50 OHM SINGLE-ENDED IMPEDANCE" at 11575.39,-310.54 h25
  text "LAYER 2 & 3 (INNER LAYERS) XX MIL WIDE, XX MIL SPACE / TRACES REQUIRE 100 OHM DIFFERENTIAL IMPEDANCE" at 11567.39,-546.26 h25
  text ".Layer_Name" at 569,-2296.49 h25
M11 Gerber Information:
  lines w10: -300,-2368.17 6300,-2368.17 ; -300,-2164.83 6302,-2164.83 ; -300,-1961.5 -300,-2571.5 3705,-2571.5 6302,-2571.5 6302,-1961.5 -299.5,-1961.5 -299.5,-2571.5 1276,-2571.5 ; 2165,-2571.5 2165,-1961.5 ; 3432,-2164.83 3432,-1961.5 ; 4272,-2164.83 4272,-1961.5 ; 4894,-2578 4894,-2375.17
  text "ALL ARTWORK VIEWED FROM TOP SIDE" at -236.5,-2093.67 h25
  text "BOARD #:" at 2240,-2093.67 h25
  text ".PRJ_Number" at 2785.5,-2093.67 h25
  text "REV:" at 3630,-2093.67 h25
  text ".PCB_Rev" at 3921.5,-2093.67 h25
  text "SVN REV:" at 4468,-2093.67 h25
  text ".VersionControl_RevNumber" at 4974,-2093.67 h25
  text "LAYER NAME =" at -236.5,-2296.49 h25
  text "TID #:" at 2240,-2297 h25
  text ".TID" at 2785.5,-2297 h25
  text "PLOT NAME =" at -236.5,-2502.34 h25
  text ".plot_File_Name" at 569,-2502.34 h25
  text "GENERATED    :" at 2242,-2502.34 h25
  text ".Print_Date" at 3111.5,-2502.34 h25
  text ".Print_Time" at 3840.5,-2502.34 h25
  text "TEXAS INSTRUMENTS" at 5105,-2502.34 h25
M12 Stackup:
  drawing of 306 lines, arcs and shapes, not listed
  text "Layer" at 9733.35,6468.5 h25
  text "Name" at 9915.81,6468.5 h25
  text "Material" at 10319.03,6468.5 h25
  text "Thickness" at 10688.94,6468.5 h25
  text "Constant" at 10971.37,6468.5 h25
  text "Board Layer Stack" at 11220.48,6468.5 h25
  text "Top Overlay" at 9915.81,6418.5 h25
  text "Top Solder" at 9915.81,6368.5 h25
  text "Solder Resist" at 10319.03,6368.5 h25
  text "0.40mil" at 10688.94,6368.5 h25
  text "3.5" at 10971.37,6368.5 h25
  text "1" at 9733.35,6318.5 h25
  text "Top Layer" at 9915.81,6318.5 h25
  text "2.80mil" at 10688.94,6318.5 h25
  text "Dielectric 1" at 9915.81,6268.5 h25
  text "FR4 370" at 10319.03,6268.5 h25
  text "11.40mil" at 10688.94,6268.5 h25
  text "4.2" at 10971.37,6268.5 h25
  text "2" at 9733.35,6218.5 h25
  text "Signal Layer 1" at 9915.81,6218.5 h25
  text "1.40mil" at 10688.94,6218.5 h25
  text "Dielectric 2" at 9915.81,6168.5 h25
  text "FR4 370" at 10319.03,6168.5 h25
  text "30.00mil" at 10688.94,6168.5 h25
  text "4.2" at 10971.37,6168.5 h25
  text "3" at 9733.35,6118.5 h25
  text "Signal Layer 2" at 9915.81,6118.5 h25
  text "1.40mil" at 10688.94,6118.5 h25
  text "Dielectric 3" at 9915.81,6068.5 h25
  text "FR4 370" at 10319.03,6068.5 h25
  text "11.40mil" at 10688.94,6068.5 h25
  text "4.2" at 10971.37,6068.5 h25
  text "4" at 9733.35,6018.5 h25
  text "Bottom Layer" at 9915.81,6018.5 h25
  text "2.80mil" at 10688.94,6018.5 h25
  text "Bottom Solder" at 9915.81,5968.5 h25
  text "Solder Resist" at 10319.03,5968.5 h25
  text "0.40mil" at 10688.94,5968.5 h25
  text "3.5" at 10971.37,5968.5 h25
  text "Bottom Overlay" at 9915.81,5918.5 h25
  text ".Layer_Name" at 569,-2296.49 h25
M13 Component Bodies Top:
  text ".Layer_Name" at 569,-2296.49 h25
M14 Component Bodies Bottom:
  text ".Layer_Name" at 569,-2296.49 h25
M15 Courtyards Top:
  text ".Layer_Name" at 569,-2296.49 h25
M16 Courtyards Bottom:
  text ".Layer_Name" at 569,-2296.49 h25
Drill Drawing:
  circle w10: c67.97,6393.6 r6.89
  circle w10: c67.97,6393.6 r11.48
  circle w10: c67.97,5980.48 r11.48
  lines w10: 56.49,5871.46 62.23,5871.46 67.97,5865.72 73.7,5871.46 79.44,5871.46 73.7,5877.2 79.44,5882.94 73.7,5882.94 67.97,5888.67 62.23,5882.94 56.49,5882.94 62.23,5877.2 56.49,5871.46 ; 56.49,5917.36 67.97,5923.1 79.44,5917.36 73.7,5928.84 79.44,5940.31 67.97,5934.58 56.49,5940.31 62.23,5928.84 56.49,5917.36 ; 56.49,6043.59 79.44,6043.59 67.97,6020.64 56.49,6043.59 ; 56.49,6078.02 62.23,6078.02 62.23,6072.28 73.7,6072.28 73.7,6078.02 79.44,6078.02 79.44,6089.5 73.7,6089.5 73.7,6095.24 62.23,6095.24 62.23,6089.5 56.49,6089.5 56.49,6078.02 ; 56.49,6146.88 79.44,6146.88 67.97,6123.92 56.49,6146.88 ; 56.49,6187.04 67.97,6175.56 79.44,6187.04 67.97,6198.52 56.49,6187.04 ; 56.49,6227.21 56.49,6232.94 62.23,6238.68 56.49,6244.42 56.49,6250.16 62.23,6250.16 67.97,6244.42 73.7,6250.16 79.44,6250.16 79.44,6244.42 73.7,6238.68 79.44,6232.94 79.44,6227.21 73.7,6227.21 67.97,6232.94 62.23,6227.21 56.49,6227.21 ; 56.49,6278.85 79.44,6278.85 79.44,6301.8 56.49,6301.8 56.49,6278.85 ; 56.49,6330.49 79.44,6330.49 79.44,6353.44 56.49,6353.44 56.49,6330.49 ; 56.49,6439.5 62.23,6439.5 62.23,6433.77 73.7,6433.77 73.7,6439.5 79.44,6439.5 79.44,6450.98 73.7,6450.98 73.7,6456.72 62.23,6456.72 62.23,6450.98 56.49,6450.98 56.49,6439.5 ; 61.08,5921.95 67.97,5925.4 74.85,5921.95 71.41,5928.84 74.85,5935.72 67.97,5932.28 61.08,5935.72 64.52,5928.84 61.08,5921.95 ; 61.08,6142.29 74.85,6142.29 67.97,6128.51 61.08,6142.29 ; 61.08,6335.08 74.85,6335.08 74.85,6348.85 61.08,6348.85 61.08,6335.08 ; 61.08,6441.8 64.52,6441.8 64.52,6438.36 71.41,6438.36 71.41,6441.8 74.85,6441.8 74.85,6448.69 71.41,6448.69 71.41,6452.13 64.52,6452.13 64.52,6448.69 61.08,6448.69 61.08,6441.8
  lines w12: 33.86,5850.23 1377.59,5850.23 ; 33.86,6469.92 1377.59,6469.92 ; 174.39,5798.59 174.39,6521.56 ; 312.5,5798.59 312.5,6521.56 ; 577.29,5798.59 577.29,6521.56 ; 685.07,5798.59 685.07,6521.56 ; 841.13,5798.59 841.13,6521.56 ; 1141.95,5798.59 1141.95,6521.56 ; 33.86,5798.59 1377.59,5798.59 1377.59,6521.56 33.86,6521.56 33.86,5798.59
  text "Symbol" at 64.84,6485.41 h30
  text "Quantity" at 189.88,6485.41 h30
  text "Finished Hole Size" at 327.99,6485.41 h30
  text "Plated" at 592.78,6485.41 h30
  text "Hole Type" at 700.56,6485.41 h30
  text "Drill Layer Pair" at 856.62,6485.41 h30
  text "Hole Tolerance" at 1157.45,6485.41 h30
  text "2" at 189.88,6433.77 h25
  text "27.56mil (0.700mm)" at 327.99,6433.77 h25
  text "NPTH" at 592.78,6433.77 h25
  text "Round" at 700.56,6433.77 h25
  text "Top Layer - Bottom Layer" at 856.62,6433.77 h25
  text "21" at 189.88,6382.13 h25
  text "7.87mil (0.200mm)" at 327.99,6382.13 h25
  text "PTH" at 592.78,6382.13 h25
  text "Round" at 700.56,6382.13 h25
  text "Top Layer - Bottom Layer" at 856.62,6382.13 h25
  text "11" at 189.88,6330.49 h25
  text "12.00mil (0.305mm)" at 327.99,6330.49 h25
  text "PTH" at 592.78,6330.49 h25
  text "Round" at 700.56,6330.49 h25
  text "Top Layer - Bottom Layer" at 856.62,6330.49 h25
  text "145" at 189.88,6278.85 h25
  text "13.78mil (0.350mm)" at 327.99,6278.85 h25
  text "PTH" at 592.78,6278.85 h25
  text "Round" at 700.56,6278.85 h25
  text "Top Layer - Bottom Layer" at 856.62,6278.85 h25
  text "47" at 189.88,6227.21 h25
  text "16.00mil (0.406mm)" at 327.99,6227.21 h25
  text "PTH" at 592.78,6227.21 h25
  text "Round" at 700.56,6227.21 h25
  text "Top Layer - Bottom Layer" at 856.62,6227.21 h25
  text "14" at 189.88,6175.56 h25
  text "40.00mil (1.016mm)" at 327.99,6175.56 h25
  text "PTH" at 592.78,6175.56 h25
  text "Round" at 700.56,6175.56 h25
  text "Top Layer - Bottom Layer" at 856.62,6175.56 h25
  text "28" at 189.88,6123.92 h25
  text "43.31mil (1.100mm)" at 327.99,6123.92 h25
  text "PTH" at 592.78,6123.92 h25
  text "Round" at 700.56,6123.92 h25
  text "Top Layer - Bottom Layer" at 856.62,6123.92 h25
  text "+/-1.97mil" at 1157.45,6123.92 h25
  text "33" at 189.88,6072.28 h25
  text "43.31mil (1.100mm)" at 327.99,6072.28 h25
  text "PTH" at 592.78,6072.28 h25
  text "Round" at 700.56,6072.28 h25
  text "Top Layer - Bottom Layer" at 856.62,6072.28 h25
  text "3" at 189.88,6020.64 h25
  text "45.28mil (1.150mm)" at 327.99,6020.64 h25
  text "PTH" at 592.78,6020.64 h25
  text "Round" at 700.56,6020.64 h25
  text "Top Layer - Bottom Layer" at 856.62,6020.64 h25
  text "6" at 189.88,5969 h25
  text "51.18mil (1.300mm)" at 327.99,5969 h25
  text "PTH" at 592.78,5969 h25
  text "Round" at 700.56,5969 h25
  text "Top Layer - Bottom Layer" at 856.62,5969 h25
  text "4" at 189.88,5917.36 h25
  text "59.06mil (1.500mm)" at 327.99,5917.36 h25
  text "PTH" at 592.78,5917.36 h25
  text "Round" at 700.56,5917.36 h25
  text "Top Layer - Bottom Layer" at 856.62,5917.36 h25
  text "6" at 189.88,5865.72 h25
  text "63.00mil (1.600mm)" at 327.99,5865.72 h25
  text "PTH" at 592.78,5865.72 h25
  text "Round" at 700.56,5865.72 h25
  text "Top Layer - Bottom Layer" at 856.62,5865.72 h25
  text "320 Total" at 189.88,5814.08 h25
  text ".Layer_Name" at 569,-2296.49 h25
Mechanical 17:
  text ".Layer_Name" at 569,-2296.49 h25
Mechanical 18:
  text ".Layer_Name" at 569,-2296.49 h25
Mechanical 19:
  text ".Layer_Name" at 569,-2296.49 h25

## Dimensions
24,304.75 to 4569,0 on M1 Board Outline
-6,-4 to 4569,0 on M2 Board Dimensions
0,0 to 4571,3249 on M2 Board Dimensions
